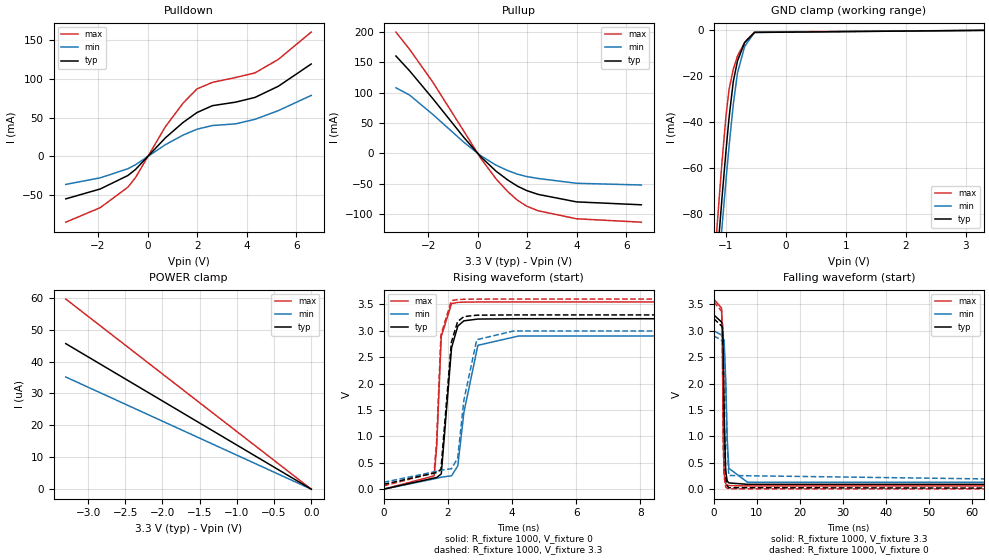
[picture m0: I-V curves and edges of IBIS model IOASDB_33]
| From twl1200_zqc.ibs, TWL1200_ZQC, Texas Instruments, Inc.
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[Model]   IOASDB_33
Model_type  I/O
Vinl=1.155
Vinh=2.145
Enable   Active-Low
Vref =   3.3
Rref =   1M
Cref =   15p
Vmeas =   1.65
| variable   typ   min   max
C_comp   3.59pF   2.93pF   4.64pF
| C_pullup   4.22pF   3.26pF   5.19pF
| C_pulldown   4.21pF   3.44pF   4.85pF
| C_tri-state   3.59pF   2.93pF   4.64pF
[Temperature Range]   40   100   -40
| Ambient temperature   25   85   -40
[Voltage range]   3.3   3   3.6
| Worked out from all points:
|   slope of the pulldown table from 0 to 0.495 V, typ, clamps not added: 29.3 ohm
|   slope of the pullup table from 0 to 0.495 V, typ, clamps not added: 24.1 ohm
|   GND clamp passes 1 mA (typ) near -0.53 V on its own axis
|   rising waveform, R_fixture 1000, V_fixture 0: 20-80 % time 221ps typ, 346ps min, 145ps max; typ from 0.003 V to 3.23 V
|   falling waveform, R_fixture 1000, V_fixture 3.3: 20-80 % time 375ps typ, 599ps min, 255ps max; typ from 3.3 V to 0.094 V
|   rising waveform, R_fixture 1000, V_fixture 3.3: 20-80 % time 215ps typ, 331ps min, 142ps max; typ from 0.094 V to 3.3 V
|   falling waveform, R_fixture 1000, V_fixture 0: 20-80 % time 370ps typ, 584ps min, 252ps max; typ from 3.23 V to 0.003 V
[GND Clamp]
| IOASDB_33
|   Voltage   I(typ)   I(min)   I(max)
-3.3V     -904.6mA   -884.4mA   -930.6mA
-1.16V    -105.2mA   -116.9mA   -90.79mA
-1.14V    -98.47mA   -110.4mA   -83.7mA
-1.105V   -86.8mA    -99.06mA   -71.53mA
-1.06V    -72.16mA   -84.8mA    -56.49mA
-995mV    -52.07mA   -64.93mA   -36.98mA
-945mV    -38.03mA   -50.49mA   -25.74mA
-875mV    -22.36mA   -32.37mA   -16.96mA
-805mV    -13.35mA   -18.54mA   -11.23mA
-685mV    -5.306mA   -6.994mA   -5.239mA
-520mV    -924.4uA   -895.8uA   -726uA
3.3V      560.6pA    3.201uA    -5.419uA
[POWER Clamp]
| IOASDB_33
|   Voltage   I(typ)   I(min)   I(max)
-3.3V     45.63uA    35.17uA    59.61uA
-1.795V   24.82uA    19.13uA    32.42uA
-1.53V    21.15uA    16.31uA    27.63uA
-1.435V   19.84uA    15.3uA     25.92uA
-1.06V    14.66uA    11.3uA     19.15uA
-745mV    10.3uA     7.944uA    13.46uA
0V        0A         0A         0A
[Pulldown]
| IOASDB_33
|   Voltage   I(typ)   I(min)   I(max)
-3.3V     -54.93mA   -36.27mA   -85.04mA
-1.91V    -42.15mA   -27.76mA   -66.25mA
-795mV    -24.76mA   -16.02mA   -39.87mA
-485mV    -16.89mA   -10.82mA   -27.31mA
715mV     23.78mA    15.01mA    38.15mA
1.43V     43.71mA    27.38mA    68.71mA
1.99V     56.48mA    34.95mA    86.98mA
2.61V     65.37mA    39.75mA    95.46mA
3.555V    69.97mA    41.95mA    101.8mA
4.33V     76.04mA    47.76mA    107.7mA
5.275V    90.5mA     59.02mA    125.2mA
6.6V      119.2mA    78.66mA    160.4mA
[Pullup]
| IOASDB_33
|   Voltage   I(typ)   I(min)   I(max)
-3.3V     160.1mA    108mA      199.4mA
-2.75V    135.8mA    95.9mA     171.1mA
-1.82V    90.5mA     64.41mA    117.7mA
-560mV    26.4mA     18.41mA    36.57mA
125mV     -5.592mA   -3.756mA   -8.169mA
740mV     -29.14mA   -19.25mA   -41.86mA
1.21V     -43.58mA   -28.1mA    -62.66mA
1.595V    -53.53mA   -33.93mA   -76.57mA
1.98V     -61.05mA   -37.98mA   -86.7mA
2.44V     -67.27mA   -41.13mA   -94.15mA
3.985V    -79.54mA   -48.98mA   -107.3mA
6.6V      -84.33mA   -51.79mA   -112.9mA
[Ramp]
| IOASDB_33
| variable   typ   min   max
dV/dt_r   1.94/2.32E-10   1.74/3.58E-10   2.13/1.50E-10
dV/dt_f   1.92/3.78E-10   1.72/6.00E-10   2.12/2.58E-10
R_load = 1000
[Rising Waveform]
| IOASDB_33
R_fixture =   1000
C_fixture =   0
L_fixture =   0
V_fixture =   0
V_fixture_min = 0
V_fixture_max = 0
|   Time   V(typ)   V(min)   V(max)
0s        3.396mV    3.432mV    3.422mV
1.575ns   214.3mV    198.5mV    255.6mV
1.65ns    222.8mV    209.5mV    793.3mV
1.795ns   291.7mV    230.6mV    2.894V
2.115ns   2.679V     256.3mV    3.513V
2.31ns    3.089V     444.2mV    3.537V
2.5ns     3.188V     1.456V     3.542V
2.935ns   3.222V     2.725V     3.545V
4.205ns   3.228V     2.901V     3.546V
240ns     3.229V     2.904V     3.547V
[Falling Waveform]
| IOASDB_33
R_fixture =   1000
C_fixture =   0
L_fixture =   0
V_fixture =   3.3
V_fixture_min = 3
V_fixture_max = 3.6
|   Time   V(typ)   V(min)   V(max)
0s        3.3V       3V         3.6V
1.815ns   3.165V     2.918V     3.428V
2.025ns   3.13V      2.881V     2.565V
2.2ns     2.626V     2.853V     975.6mV
2.39ns    1.49V      2.827V     309.8mV
2.765ns   343.7mV    2.084V     104.2mV
3.12ns    156.5mV    957.7mV    81.31mV
3.5ns     122mV      397.4mV    71.42mV
7.835ns   94.72mV    134.3mV    64.79mV
240ns     94.5mV     132.6mV    64.78mV
[Rising Waveform]
| IOASDB_33
R_fixture =   1000
C_fixture =   0
L_fixture =   0
V_fixture =   3.3
V_fixture_min = 3
V_fixture_max = 3.6
|   Time   V(typ)   V(min)   V(max)
0s        94.5mV     132.6mV    64.78mV
1.57ns    307.7mV    331.1mV    313.9mV
1.65ns    317mV      343mV      900.9mV
1.785ns   378.2mV    362.7mV    2.924V
2.11ns    2.783V     389.8mV    3.57V
2.305ns   3.175V     586.3mV    3.591V
2.5ns     3.268V     1.69V      3.596V
2.9ns     3.295V     2.831V     3.599V
4.055ns   3.3V       2.997V     3.6V
240ns     3.3V       3V         3.6V
[Falling Waveform]
| IOASDB_33
R_fixture =   1000
C_fixture =   0
L_fixture =   0
V_fixture =   0
V_fixture_min = 0
V_fixture_max = 0
|   Time   V(typ)   V(min)   V(max)
0s        3.229V     2.904V     3.547V
1.815ns   3.091V     2.821V     3.373V
1.92ns    3.075V     2.802V     3.182V
2.025ns   3.056V     2.783V     2.478V
2.19ns    2.583V     2.756V     944.5mV
2.385ns   1.386V     2.728V     249.4mV
2.755ns   256.4mV    1.965V     43.37mV
3.1ns     67.42mV    833.6mV    20.23mV
3.49ns    30.93mV    262.2mV    10.02mV
240ns     3.396mV    3.432mV    3.422mV
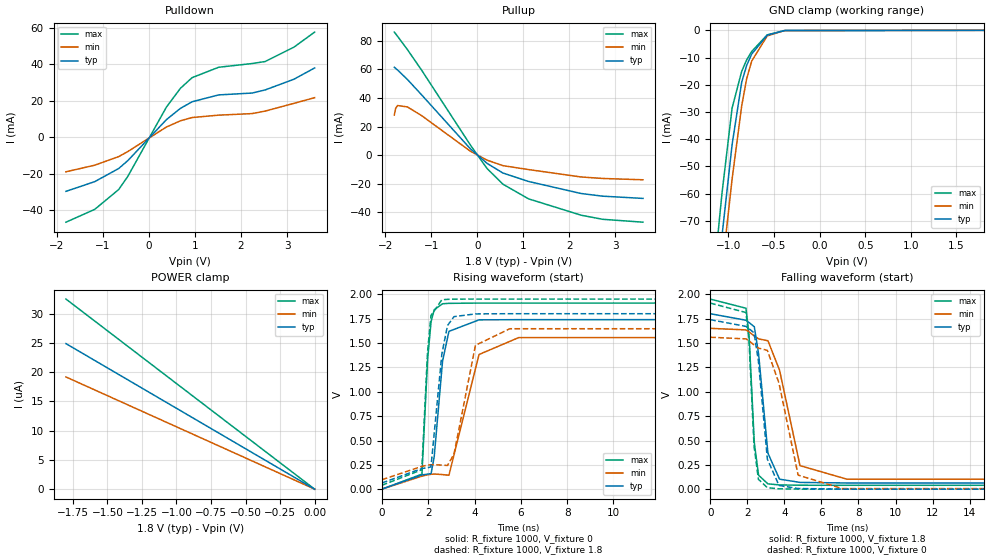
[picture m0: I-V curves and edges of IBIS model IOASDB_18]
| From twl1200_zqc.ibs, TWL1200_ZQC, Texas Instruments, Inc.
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[Model]   IOASDB_18
Model_type  I/O
Vinl=0.63
Vinh=1.17
Enable   Active-Low
Vref =   1.8
Rref =   1M
Cref =   15p
Vmeas =   0.9
| variable   typ   min   max
C_comp   3.84pF   3.22pF   4.64pF
| C_pullup   4.55pF   3.55pF   5.13pF
| C_pulldown   4.59pF   3.85pF   5.00pF
| C_tri-state   3.84pF   3.22pF   4.64pF
[Temperature Range]   40   100   -40
| Ambient temperature   25   85   -40
[Voltage range]   1.8   1.65   1.95
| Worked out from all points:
|   slope of the pulldown table from 0 to 0.27 V, typ, clamps not added: 38.1 ohm
|   slope of the pullup table from 0 to 0.27 V, typ, clamps not added: 38.7 ohm
|   GND clamp passes 1 mA (typ) near -0.53 V on its own axis
|   rising waveform, R_fixture 1000, V_fixture 0: 20-80 % time 402ps typ, 765ps min, 238ps max; typ from 0.002 V to 1.74 V
|   falling waveform, R_fixture 1000, V_fixture 1.8: 20-80 % time 507ps typ, 896ps min, 302ps max; typ from 1.8 V to 0.065 V
|   rising waveform, R_fixture 1000, V_fixture 1.8: 20-80 % time 379ps typ, 693ps min, 229ps max; typ from 0.065 V to 1.8 V
|   falling waveform, R_fixture 1000, V_fixture 0: 20-80 % time 493ps typ, 859ps min, 296ps max; typ from 1.74 V to 0.002 V
[GND Clamp]
| IOASDB_18
|   Voltage   I(typ)   I(min)   I(max)
-1.8V     -335.7mA   -338mA     -334.1mA
-1.155V   -103.5mA   -115.2mA   -88.97mA
-1.14V    -98.45mA   -110.3mA   -83.67mA
-1.1V     -85.13mA   -97.43mA   -69.79mA
-1.07V    -75.34mA   -87.92mA   -59.72mA
-960mV    -42.04mA   -54.71mA   -28.58mA
-855mV    -19.11mA   -27.85mA   -15.11mA
-800mV    -12.87mA   -17.76mA   -10.85mA
-745mV    -8.721mA   -11.32mA   -7.783mA
-575mV    -1.8mA     -2.053mA   -1.671mA
-385mV    -87.43uA   -83.76uA   -64.04uA
1.8V      356.9pA    1.602uA    -2.709uA
[POWER Clamp]
| IOASDB_18
|   Voltage   I(typ)   I(min)   I(max)
-1.8V     24.89uA    19.19uA    32.51uA
-205mV    2.835uA    2.188uA    3.703uA
-60mV     831.5nA    644.8nA    1.085uA
0V        0A         0A         0A
[Pulldown]
| IOASDB_18
|   Voltage   I(typ)   I(min)   I(max)
-1.8V     -29.66mA   -18.94mA   -46.6mA
-1.175V   -24.35mA   -15.32mA   -39.55mA
-655mV    -17.14mA   -10.59mA   -28.68mA
-455mV    -12.77mA   -7.807mA   -21.37mA
380mV     9.655mA    5.622mA    16.53mA
685mV     15.86mA    9.052mA    26.87mA
940mV     19.51mA    10.84mA    32.75mA
1.515V    23.26mA    12.15mA    38.43mA
2.24V     24.28mA    13mA       40.48mA
2.525V    25.99mA    14.38mA    41.58mA
3.15V     31.87mA    18.62mA    49.47mA
3.6V      38.06mA    21.75mA    57.74mA
[Pullup]
| IOASDB_18
|   Voltage   I(typ)   I(min)   I(max)
-1.8V     61.48mA    28.05mA    86.04mA
-1.77V    60.69mA    32.84mA    84.81mA
-1.73V    59.58mA    34.73mA    83.15mA
-1.515V   52.93mA    33.75mA    73.8mA
-1.21V    42.31mA    27.76mA    59.59mA
-150mV    4.562mA    2.859mA    7.243mA
215mV     -5.706mA   -3.438mA   -9.322mA
560mV     -12.45mA   -7.274mA   -20.24mA
1.115V    -18.32mA   -10.02mA   -30.47mA
2.255V    -26.73mA   -15.18mA   -41.88mA
2.725V    -28.6mA    -16.23mA   -44.77mA
3.6V      -30.17mA   -17.15mA   -46.78mA
[Ramp]
| IOASDB_18
| variable   typ   min   max
dV/dt_r   1.04/4.10E-10   0.93/7.70E-10   1.14/2.50E-10
dV/dt_f   1.04/5.11E-10   0.93/8.99E-10   1.14/3.07E-10
R_load = 1000
[Rising Waveform]
| IOASDB_18
R_fixture =   1000
C_fixture =   0
L_fixture =   0
V_fixture =   0
V_fixture_min = 0
V_fixture_max = 0
|   Time   V(typ)   V(min)   V(max)
0s        2.322mV    2.513mV    2.203mV
1.73ns    147.9mV    135.7mV    156mV
1.975ns   156.7mV    149.4mV    1.333V
2.125ns   161mV      154.6mV    1.719V
2.26ns    334.8mV    157.3mV    1.84V
2.62ns    1.314V     151.7mV    1.902V
2.895ns   1.619V     144.6mV    1.906V
4.195ns   1.737V     1.382V     1.909V
5.905ns   1.739V     1.555V     1.909V
239.9ns   1.739V     1.559V     1.909V
[Falling Waveform]
| IOASDB_18
R_fixture =   1000
C_fixture =   0
L_fixture =   0
V_fixture =   1.8
V_fixture_min = 1.65
V_fixture_max = 1.95
|   Time   V(typ)   V(min)   V(max)
0s        1.8V       1.65V      1.95V
1.93ns    1.733V     1.634V     1.856V
2.1ns     1.709V     1.613V     1.57V
2.38ns    1.666V     1.572V     477.6mV
2.61ns    1.391V     1.542V     145.2mV
3.115ns   371.3mV    1.523V     56.38mV
3.74ns    104.8mV    1.223V     45.63mV
4.845ns   71.35mV    243.4mV    42.53mV
7.38ns    65.72mV    104.3mV    42mV
239.9ns   65.27mV    98.8mV     41.98mV
[Rising Waveform]
| IOASDB_18
R_fixture =   1000
C_fixture =   0
L_fixture =   0
V_fixture =   1.8
V_fixture_min = 1.65
V_fixture_max = 1.95
|   Time   V(typ)   V(min)   V(max)
0s        65.27mV    98.8mV     41.98mV
1.725ns   213.4mV    235.5mV    201.3mV
1.97ns    222.1mV    248.5mV    1.401V
2.12ns    229.7mV    252.8mV    1.781V
2.59ns    1.387V     249mV      1.943V
2.835ns   1.679V     244.9mV    1.947V
3.115ns   1.77V      362.5mV    1.949V
4.04ns    1.798V     1.476V     1.95V
5.525ns   1.8V       1.646V     1.95V
239.9ns   1.8V       1.65V      1.95V
[Falling Waveform]
| IOASDB_18
R_fixture =   1000
C_fixture =   0
L_fixture =   0
V_fixture =   0
V_fixture_min = 0
V_fixture_max = 0
|   Time   V(typ)   V(min)   V(max)
0s        1.739V     1.559V     1.909V
1.93ns    1.67V      1.542V     1.812V
2.09ns    1.647V     1.522V     1.54V
2.365ns   1.604V     1.48V      446.3mV
2.6ns     1.317V     1.448V     103.8mV
3.085ns   310mV      1.424V     16.99mV
3.71ns    40.72mV    1.09V      5.875mV
4.745ns   8.732mV    146.1mV    2.818mV
7.12ns    2.841mV    8.381mV    2.227mV
239.9ns   2.322mV    2.513mV    2.203mV
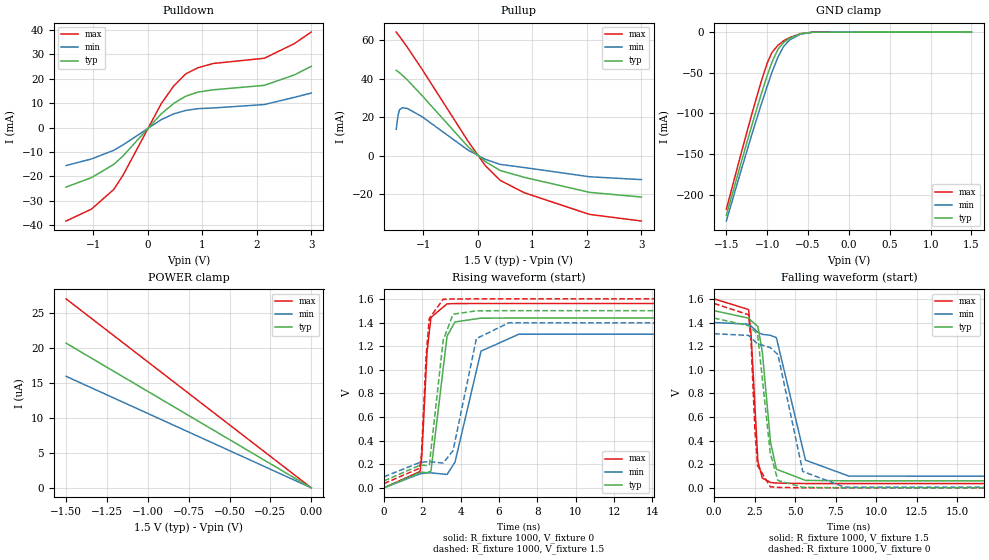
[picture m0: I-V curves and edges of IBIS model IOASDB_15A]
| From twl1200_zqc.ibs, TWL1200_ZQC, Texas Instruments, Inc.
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[Model]   IOASDB_15A
Model_type  I/O
Vinl=0.525
Vinh=0.975
Enable   Active-Low
Vref =   1.5
Rref =   1M
Cref =   15p
Vmeas =   0.75
| variable   typ   min   max
C_comp   3.91pF   3.32pF   4.64pF
| C_pullup   4.62pF   3.63pF   5.10pF
| C_pulldown   4.69pF   3.93pF   5.10pF
| C_tri-state   3.91pF   3.32pF   4.64pF
[Temperature Range]   40   100   -40
| Ambient temperature   25   85   -40
[Voltage range]   1.5   1.4   1.6
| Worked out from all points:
|   slope of the pulldown table from 0 to 0.225 V, typ, clamps not added: 43.2 ohm
|   slope of the pullup table from 0 to 0.225 V, typ, clamps not added: 47.4 ohm
|   GND clamp passes 1 mA (typ) near -0.53 V on its own axis
|   rising waveform, R_fixture 1000, V_fixture 0: 20-80 % time 531ps typ, 1.01ns min, 305ps max; typ from 0.002 V to 1.44 V
|   falling waveform, R_fixture 1000, V_fixture 1.5: 20-80 % time 597ps typ, 1.07ns min, 328ps max; typ from 1.5 V to 0.061 V
|   rising waveform, R_fixture 1000, V_fixture 1.5: 20-80 % time 494ps typ, 895ps min, 292ps max; typ from 0.061 V to 1.5 V
|   falling waveform, R_fixture 1000, V_fixture 0: 20-80 % time 578ps typ, 1.01ns min, 320ps max; typ from 1.44 V to 0.002 V
[GND Clamp]
| IOASDB_15A
|   Voltage   I(typ)   I(min)   I(max)
-1.5V     -225.5mA   -232.3mA   -217.8mA
-1.315V   -159mA     -168.6mA   -147.6mA
-1.175V   -110.3mA   -121.8mA   -96.11mA
-1.07V    -75.34mA   -87.91mA   -59.72mA
-1V       -53.52mA   -66.39mA   -38.29mA
-940mV    -36.69mA   -49.08mA   -24.84mA
-870mV    -21.47mA   -31.19mA   -16.46mA
-800mV    -12.87mA   -17.76mA   -10.85mA
-725mV    -7.452mA   -9.662mA   -6.863mA
-590mV    -2.11mA    -2.522mA   -2.033mA
-445mV    -250.8uA   -238.2uA   -152.1uA
1.5V      322.6pA    1.07uA     -1.806uA
[POWER Clamp]
| IOASDB_15A
|   Voltage   I(typ)   I(min)   I(max)
-1.5V     20.74uA    15.99uA    27.09uA
-60mV     831.2nA    644.6nA    1.085uA
-5mV      69.54nA    55.09nA    90.39nA
0V        0A         0A         0A
[Pulldown]
| IOASDB_15A
|   Voltage   I(typ)   I(min)   I(max)
-1.5V     -24.33mA   -15.51mA   -38.22mA
-1.035V   -20.48mA   -12.84mA   -33.36mA
-625mV    -15.07mA   -9.288mA   -25.31mA
-450mV    -11.5mA    -7.006mA   -19.3mA
245mV     5.598mA    3.228mA    9.739mA
475mV     9.882mA    5.606mA    17.01mA
695mV     12.83mA    7.023mA    21.96mA
920mV     14.52mA    7.745mA    24.48mA
1.2V      15.46mA    8.034mA    26.23mA
2.14V     17.29mA    9.424mA    28.38mA
2.69V     21.55mA    12.38mA    34.36mA
3V        25.05mA    14.12mA    39.1mA
[Pullup]
| IOASDB_15A
|   Voltage   I(typ)   I(min)   I(max)
-1.5V     44.25mA    13.7mA     64.07mA
-1.465V   43.53mA    21.15mA    62.77mA
-1.44V    42.97mA    23.84mA    61.83mA
-1.385V   41.65mA    24.88mA    59.71mA
-1.295V   39.27mA    24.5mA     56.15mA
-1.03V    31.3mA     20.32mA    45mA
-180mV    4.667mA    2.918mA    7.495mA
135mV     -3.014mA   -1.803mA   -5.058mA
410mV     -7.634mA   -4.45mA    -12.73mA
850mV     -11.14mA   -6.08mA    -19.1mA
2.05V     -18.92mA   -10.84mA   -30.33mA
3V        -21.34mA   -12.32mA   -33.75mA
[Ramp]
| IOASDB_15A
| variable   typ   min   max
dV/dt_r   0.86/5.37E-10   0.78/1.01E-09   0.94/3.19E-10
dV/dt_f   0.86/6.04E-10   0.78/1.07E-09   0.94/3.40E-10
R_load = 1000
[Rising Waveform]
| IOASDB_15A
R_fixture =   1000
C_fixture =   0
L_fixture =   0
V_fixture =   0
V_fixture_min = 0
V_fixture_max = 0
|   Time   V(typ)   V(min)   V(max)
0s        2.155mV    2.395mV    1.989mV
1.885ns   131.1mV    120.9mV    140.8mV
1.975ns   133.6mV    123.4mV    272.9mV
2.245ns   129.9mV    127.5mV    1.146V
2.45ns    143.4mV    128.9mV    1.443V
3.29ns    1.285V     115.2mV    1.558V
3.705ns   1.405V     219.4mV    1.56V
5.06ns    1.437V     1.158V     1.561V
7.03ns    1.438V     1.301V     1.561V
239.9ns   1.438V     1.305V     1.561V
[Falling Waveform]
| IOASDB_15A
R_fixture =   1000
C_fixture =   0
L_fixture =   0
V_fixture =   1.5
V_fixture_min = 1.4
V_fixture_max = 1.6
|   Time   V(typ)   V(min)   V(max)
0s        1.5V       1.4V       1.6V
2.125ns   1.437V     1.386V     1.51V
2.285ns   1.415V     1.369V     1.289V
2.7ns     1.367V     1.318V     225.7mV
2.975ns   1.15V      1.3V       84.3mV
3.48ns    387.2mV    1.292V     47.8mV
3.84ns    159.9mV    1.272V     42.66mV
5.635ns   64.87mV    235.8mV    38.32mV
8.31ns    61.28mV    101.3mV    38.08mV
239.9ns   60.96mV    95.19mV    38.07mV
[Rising Waveform]
| IOASDB_15A
R_fixture =   1000
C_fixture =   0
L_fixture =   0
V_fixture =   1.5
V_fixture_min = 1.4
V_fixture_max = 1.6
|   Time   V(typ)   V(min)   V(max)
0s        60.96mV    95.19mV    38.07mV
1.85ns    191.2mV    215.5mV    167mV
1.955ns   193.8mV    218.3mV    284.8mV
2.2ns     191.3mV    222mV      1.121V
2.365ns   194.8mV    223.3mV    1.435V
3.09ns    1.252V     211.8mV    1.597V
3.605ns   1.47V      317.5mV    1.599V
4.82ns    1.499V     1.264V     1.6V
6.505ns   1.5V       1.397V     1.6V
239.9ns   1.5V       1.4V       1.6V
[Falling Waveform]
| IOASDB_15A
R_fixture =   1000
C_fixture =   0
L_fixture =   0
V_fixture =   0
V_fixture_min = 0
V_fixture_max = 0
|   Time   V(typ)   V(min)   V(max)
0s        1.438V     1.305V     1.561V
2.125ns   1.373V     1.291V     1.466V
2.27ns    1.352V     1.274V     1.261V
2.52ns    1.324V     1.239V     479.7mV
2.68ns    1.301V     1.22V      189.6mV
3.465ns   293.8mV    1.188V     11.19mV
3.935ns   64.38mV    1.129V     5.715mV
5.465ns   6.425mV    140.9mV    2.29mV
8.035ns   2.517mV    8.136mV    1.999mV
239.9ns   2.155mV    2.395mV    1.989mV
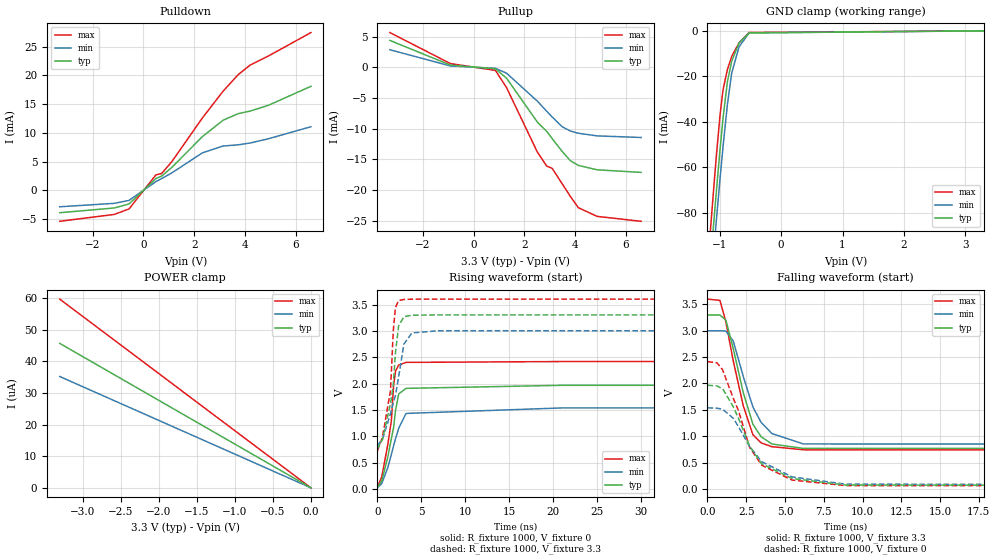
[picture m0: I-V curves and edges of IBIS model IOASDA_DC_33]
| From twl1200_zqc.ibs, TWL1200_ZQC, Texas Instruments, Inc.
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[Model]   IOASDA_DC_33
Model_type  I/O
Vinl=1.155
Vinh=2.145
Enable   Active-Low
Vref =   3.3
Rref =   1M
Cref =   15p
Vmeas =   1.65
| variable   typ   min   max
C_comp   3.59pF   2.93pF   4.64pF
| C_pullup   3.59pF   2.92pF   4.58pF
| C_pulldown   3.88pF   3.06pF   4.87pF
| C_tri-state   3.59pF   2.93pF   4.64pF
[Temperature Range]   40   100   -40
| Ambient temperature   25   85   -40
[Voltage range]   3.3   3   3.6
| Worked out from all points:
|   slope of the pulldown table from 0 to 0.495 V, typ, clamps not added: 231 ohm
|   slope of the pullup table from 0 to 0.495 V, typ, clamps not added: 4.28 kohm
|   GND clamp passes 1 mA (typ) near -0.53 V on its own axis
|   rising waveform, R_fixture 1000, V_fixture 0: 20-80 % time 1.19ns typ, 1.53ns min, 990ps max; typ from 0.023 V to 1.97 V
|   falling waveform, R_fixture 1000, V_fixture 3.3: 20-80 % time 1.31ns typ, 1.55ns min, 1.27ns max; typ from 3.3 V to 0.754 V
|   rising waveform, R_fixture 1000, V_fixture 3.3: 20-80 % time 1.1ns typ, 1.55ns min, 881ps max; typ from 0.754 V to 3.3 V
|   falling waveform, R_fixture 1000, V_fixture 0: 20-80 % time 2.13ns typ, 2.6ns min, 1.88ns max; typ from 1.97 V to 0.023 V
[GND Clamp]
| IOASDA_DC_33
|   Voltage   I(typ)   I(min)   I(max)
-3.3V     -904.6mA   -884.4mA   -930.6mA
-1.16V    -105.2mA   -116.9mA   -90.79mA
-1.14V    -98.47mA   -110.4mA   -83.7mA
-1.105V   -86.8mA    -99.06mA   -71.53mA
-1.06V    -72.16mA   -84.8mA    -56.49mA
-995mV    -52.07mA   -64.93mA   -36.98mA
-945mV    -38.03mA   -50.49mA   -25.74mA
-875mV    -22.36mA   -32.37mA   -16.96mA
-805mV    -13.35mA   -18.54mA   -11.23mA
-685mV    -5.306mA   -6.994mA   -5.239mA
-520mV    -924.4uA   -895.8uA   -726uA
3.3V      560.6pA    3.201uA    -5.419uA
[POWER Clamp]
| IOASDA_DC_33
|   Voltage   I(typ)   I(min)   I(max)
-3.3V     45.63uA    35.17uA    59.61uA
-1.795V   24.82uA    19.13uA    32.42uA
-1.53V    21.15uA    16.31uA    27.63uA
-1.435V   19.84uA    15.3uA     25.92uA
-1.06V    14.66uA    11.3uA     19.15uA
-745mV    10.3uA     7.944uA    13.46uA
0V        0A         0A         0A
[Pulldown]
| IOASDA_DC_33
|   Voltage   I(typ)   I(min)   I(max)
-3.3V     -3.9mA     -2.867mA   -5.392mA
-1.145V   -3.071mA   -2.265mA   -4.194mA
-570mV    -2.374mA   -1.756mA   -3.24mA
490mV     2.043mA    1.513mA    2.68mA
715mV     2.469mA    2.037mA    2.924mA
1.11V     3.956mA    3.012mA    4.939mA
2.33V     9.373mA    6.537mA    12.64mA
3.145V    12.21mA    7.704mA    17.28mA
3.735V    13.34mA    7.914mA    20.13mA
4.195V    13.77mA    8.219mA    21.76mA
4.925V    14.79mA    8.967mA    23.37mA
6.6V      18.09mA    11.06mA    27.44mA
[Pullup]
| IOASDA_DC_33
|   Voltage   I(typ)   I(min)   I(max)
-3.3V     4.399mA    2.88mA     5.68mA
-915mV    378.9uA    237.3uA    624uA
860mV     -228.3uA   -143uA     -486.4uA
1.3V      -1.764mA   -946.4uA   -3.307mA
2.515V    -8.924mA   -5.506mA   -13.82mA
2.885V    -10.44mA   -7.158mA   -16.1mA
3.095V    -11.6mA    -8.077mA   -16.44mA
3.49V     -13.69mA   -9.666mA   -18.96mA
3.815V    -15.21mA   -10.37mA   -21.04mA
4.13V     -15.97mA   -10.73mA   -22.87mA
4.87V     -16.69mA   -11.16mA   -24.28mA
6.6V      -17.11mA   -11.42mA   -25.08mA
[Ramp]
| IOASDA_DC_33
| variable   typ   min   max
dV/dt_r   1.17/1.20E-09   0.91/1.53E-09   1.43/9.92E-10
dV/dt_f   1.53/1.31E-09   1.31/1.56E-09   1.73/1.27E-09
R_load = 1000
[Rising Waveform]
| IOASDA_DC_33
R_fixture =   1000
C_fixture =   0
L_fixture =   0
V_fixture =   0
V_fixture_min = 0
V_fixture_max = 0
|   Time   V(typ)   V(min)   V(max)
0s        22.96mV    18.97mV    29.38mV
505ps     154.5mV    100.8mV    227.5mV
1.19ns    602mV      403mV      838.9mV
1.595ns   950.1mV    650mV      1.289V
1.855ns   1.165V     822.7mV    1.963V
2.07ns    1.489V     950.3mV    2.236V
2.44ns    1.804V     1.154V     2.351V
3.27ns    1.908V     1.432V     2.401V
21.1ns    1.966V     1.537V     2.417V
240ns     1.966V     1.538V     2.416V
[Falling Waveform]
| IOASDA_DC_33
R_fixture =   1000
C_fixture =   0
L_fixture =   0
V_fixture =   3.3
V_fixture_min = 3
V_fixture_max = 3.6
|   Time   V(typ)   V(min)   V(max)
0s        3.3V       3V         3.6V
805ps     3.298V     3V         3.576V
1.19ns    3.201V     2.994V     3.169V
1.66ns    2.666V     2.809V     2.434V
2.305ns   1.831V     2.138V     1.581V
2.93ns    1.228V     1.554V     1.028V
3.455ns   992mV      1.265V     874.3mV
4.155ns   851.1mV    1.05V      800.2mV
6.185ns   768.2mV    852.4mV    742.3mV
240ns     753.8mV    823.6mV    717.8mV
[Rising Waveform]
| IOASDA_DC_33
R_fixture =   1000
C_fixture =   0
L_fixture =   0
V_fixture =   3.3
V_fixture_min = 3
V_fixture_max = 3.6
|   Time   V(typ)   V(min)   V(max)
0s        753.8mV    823.6mV    717.8mV
590ps     940.2mV    944.2mV    986.9mV
1.495ns   1.615V     1.425V     1.863V
1.815ns   1.966V     1.632V     2.993V
2.055ns   2.57V      1.766V     3.438V
2.42ns    3.092V     2.123V     3.574V
3.025ns   3.268V     2.748V     3.596V
3.93ns    3.296V     2.96V      3.601V
6.91ns    3.303V     3.002V     3.602V
240ns     3.3V       3V         3.6V
[Falling Waveform]
| IOASDA_DC_33
R_fixture =   1000
C_fixture =   0
L_fixture =   0
V_fixture =   0
V_fixture_min = 0
V_fixture_max = 0
|   Time   V(typ)   V(min)   V(max)
0s        1.966V     1.538V     2.416V
615ps     1.953V     1.53V      2.391V
975ps     1.902V     1.512V     2.262V
1.66ns    1.562V     1.341V     1.724V
2ns       1.341V     1.181V     1.485V
2.72ns    810.1mV    804.2mV    787.3mV
3.5ns     476mV      515.4mV    448.6mV
5.46ns    197.4mV    227.1mV    166.9mV
8.91ns    72.84mV    89.21mV    62.21mV
240ns     23.3mV     19.32mV    29.81mV
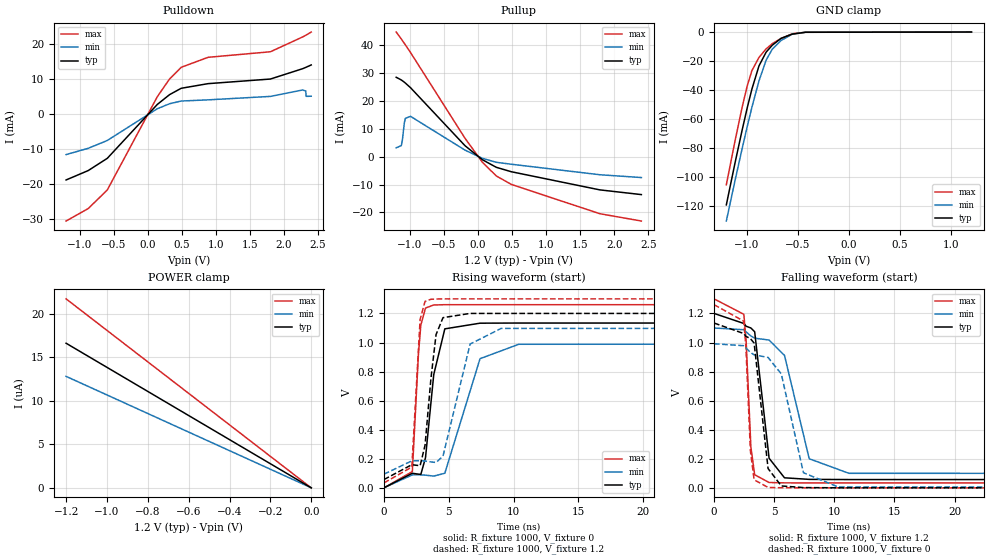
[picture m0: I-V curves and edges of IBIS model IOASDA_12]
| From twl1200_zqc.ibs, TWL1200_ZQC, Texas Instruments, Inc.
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[Model]   IOASDA_12
Model_type  I/O
Vinl=0.24
Vinh=0.96
Enable   Active-Low
Vref =   1.2
Rref =   1M
Cref =   15p
Vmeas =   0.6
| variable   typ   min   max
C_comp   3.98pF   3.44pF   4.66pF
| C_pullup   4.69pF   3.74pF   5.10pF
| C_pulldown   4.78pF   3.91pF   5.20pF
| C_tri-state   3.98pF   3.44pF   4.66pF
[Temperature Range]   40   100   -40
| Ambient temperature   25   85   -40
[Voltage range]   1.2   1.1   1.3
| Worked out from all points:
|   slope of the pulldown table from 0 to 0.18 V, typ, clamps not added: 53.1 ohm
|   slope of the pullup table from 0 to 0.18 V, typ, clamps not added: 64.5 ohm
|   GND clamp passes 1 mA (typ) near -0.53 V on its own axis
|   rising waveform, R_fixture 1000, V_fixture 0: 20-80 % time 792ps typ, 1.7ns min, 404ps max; typ from 0.002 V to 1.13 V
|   falling waveform, R_fixture 1000, V_fixture 1.2: 20-80 % time 780ps typ, 1.54ns min, 414ps max; typ from 1.2 V to 0.059 V
|   rising waveform, R_fixture 1000, V_fixture 1.2: 20-80 % time 714ps typ, 1.43ns min, 379ps max; typ from 0.059 V to 1.2 V
|   falling waveform, R_fixture 1000, V_fixture 0: 20-80 % time 749ps typ, 1.44ns min, 401ps max; typ from 1.13 V to 0.002 V
[GND Clamp]
| IOASDA_12
|   Voltage   I(typ)   I(min)   I(max)
-1.2V     -118.9mA   -130mA     -105.1mA
-1.115V   -90.07mA   -102.2mA   -74.93mA
-1.045V   -67.35mA   -80.09mA   -51.64mA
-995mV    -52.03mA   -64.9mA    -36.94mA
-950mV    -39.32mA   -51.86mA   -26.6mA
-880mV    -23.22mA   -33.52mA   -17.4mA
-810mV    -13.78mA   -19.31mA   -11.53mA
-750mV    -9.045mA   -11.77mA   -8.009mA
-665mV    -4.38mA    -5.831mA   -4.423mA
-555mV    -1.418mA   -1.522mA   -1.23mA
-425mV    -166.4uA   -161.6uA   -98.99uA
1.2V      289.9pA    1.07uA     -1.806uA
[POWER Clamp]
| IOASDA_12
|   Voltage   I(typ)   I(min)   I(max)
-1.2V     16.59uA    12.79uA    21.68uA
-60mV     831nA      644.3nA    1.084uA
-5mV      69.5nA     55.02nA    90.38nA
0V        0A         0A         0A
[Pulldown]
| IOASDA_12
|   Voltage   I(typ)   I(min)   I(max)
-1.2V     -18.88mA   -11.64mA   -30.59mA
-875mV    -16.2mA    -9.853mA   -27.04mA
-595mV    -12.71mA   -7.617mA   -21.74mA
140mV     2.672mA    1.446mA    4.878mA
320mV     5.463mA    2.867mA    9.939mA
490mV     7.271mA    3.638mA    13.25mA
885mV     8.596mA    3.97mA     16.11mA
1.8V      9.909mA    4.956mA    17.69mA
2.275V    12.87mA    6.799mA    21.93mA
2.32V     13.24mA    6.483mA    22.4mA
2.325V    13.28mA    4.966mA    22.45mA
2.4V      13.93mA    5.007mA    23.32mA
[Pullup]
| IOASDA_12
|   Voltage   I(typ)   I(min)   I(max)
-1.2V     28.37mA    3.135mA    44.56mA
-1.125V   27.41mA    3.923mA    42.05mA
-1.11V    27.15mA    5.792mA    41.53mA
-1.08V    26.59mA    12.16mA    40.49mA
-1.065V   26.29mA    13.7mA     39.95mA
-990mV    24.65mA    14.4mA     37.24mA
-190mV    3.9mA      2.315mA    6.56mA
65mV      -1.117mA   -620.4uA   -2.013mA
270mV     -3.838mA   -2.052mA   -6.935mA
490mV     -5.42mA    -2.732mA   -9.944mA
1.79V     -11.91mA   -6.499mA   -20.44mA
2.4V      -13.6mA    -7.5mA     -23.05mA
[Ramp]
| IOASDA_12
| variable   typ   min   max
dV/dt_r   0.68/7.97E-10   0.59/1.71E-09   0.75/4.09E-10
dV/dt_f   0.68/7.85E-10   0.60/1.54E-09   0.76/4.20E-10
R_load = 1000
[Rising Waveform]
| IOASDA_12
R_fixture =   1000
C_fixture =   0
L_fixture =   0
V_fixture =   0
V_fixture_min = 0
V_fixture_max = 0
|   Time   V(typ)   V(min)   V(max)
0s        2.048mV    2.342mV    1.853mV
2.19ns    102.1mV    90.83mV    113.5mV
2.66ns    96.05mV    91.57mV    919.7mV
2.845ns   94.13mV    91.11mV    1.12V
3.205ns   208.8mV    89.03mV    1.237V
3.84ns    779.6mV    82.66mV    1.258V
4.695ns   1.094V     102.1mV    1.26V
7.41ns    1.133V     889mV      1.26V
10.4ns    1.134V     988.2mV    1.26V
239.9ns   1.134V     991.6mV    1.26V
[Falling Waveform]
| IOASDA_12
R_fixture =   1000
C_fixture =   0
L_fixture =   0
V_fixture =   1.2
V_fixture_min = 1.1
V_fixture_max = 1.3
|   Time   V(typ)   V(min)   V(max)
0s        1.2V       1.1V       1.3V
2.475ns   1.131V     1.088V     1.194V
2.665ns   1.112V     1.073V     1.012V
3.06ns    1.1V       1.045V     282.2mV
3.375ns   1.074V     1.03V      91.87mV
4.575ns   205mV      1.017V     38.54mV
5.855ns   70.83mV    911.6mV    36.16mV
7.91ns    60.08mV    201.8mV    35.79mV
11.21ns   58.84mV    101.7mV    35.76mV
239.9ns   58.75mV    95.77mV    35.76mV
[Rising Waveform]
| IOASDA_12
R_fixture =   1000
C_fixture =   0
L_fixture =   0
V_fixture =   1.2
V_fixture_min = 1.1
V_fixture_max = 1.3
|   Time   V(typ)   V(min)   V(max)
0s        58.75mV    95.77mV    35.76mV
2.15ns    160.9mV    187.1mV    144.8mV
2.79ns    153.8mV    188.8mV    1.159V
3.17ns    295.1mV    185.8mV    1.283V
3.625ns   754.1mV    179.9mV    1.297V
4.02ns    1.055V     175.9mV    1.299V
4.555ns   1.171V     219.9mV    1.3V
6.645ns   1.2V       989.4mV    1.3V
9.035ns   1.2V       1.097V     1.3V
239.9ns   1.2V       1.1V       1.3V
[Falling Waveform]
| IOASDA_12
R_fixture =   1000
C_fixture =   0
L_fixture =   0
V_fixture =   0
V_fixture_min = 0
V_fixture_max = 0
|   Time   V(typ)   V(min)   V(max)
0s        1.134V     991.6mV    1.26V
2.465ns   1.062V     978.2mV    1.147V
2.64ns    1.043V     963.6mV    978.8mV
3.02ns    1.027V     932.2mV    255.7mV
3.33ns    996.1mV    915.4mV    57.11mV
4.49ns    134.4mV    897.6mV    4.702mV
5.59ns    14.96mV    784.3mV    2.374mV
7.43ns    3.654mV    105.6mV    1.898mV
10.32ns   2.195mV    7.983mV    1.854mV
239.9ns   2.048mV    2.342mV    1.853mV
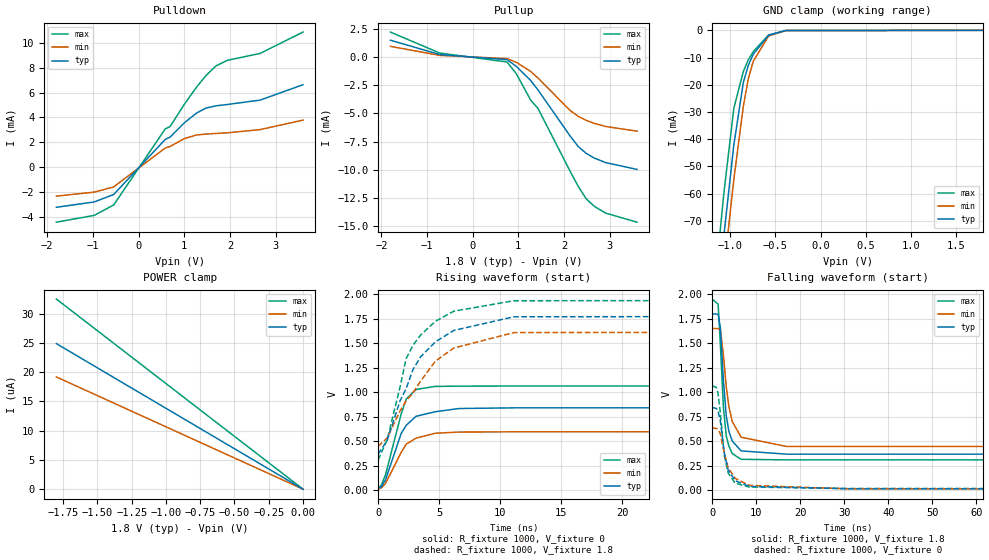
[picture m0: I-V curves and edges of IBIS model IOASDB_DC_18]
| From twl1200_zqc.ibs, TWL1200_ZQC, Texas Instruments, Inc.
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[Model]   IOASDB_DC_18
Model_type  I/O
Vinl=0.63
Vinh=1.17
Enable   Active-Low
Vref =   1.8
Rref =   1M
Cref =   15p
Vmeas =   0.9
| variable   typ   min   max
C_comp   3.84pF   3.22pF   4.64pF
| C_pullup   3.82pF   3.21pF   4.41pF
| C_pulldown   4.14pF   3.41pF   4.86pF
| C_tri-state   3.84pF   3.22pF   4.64pF
[Temperature Range]   40   100   -40
| Ambient temperature   25   85   -40
[Voltage range]   1.8   1.65   1.95
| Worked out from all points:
|   slope of the pulldown table from 0 to 0.27 V, typ, clamps not added: 244 ohm
|   slope of the pullup table from 0 to 0.27 V, typ, clamps not added: 4.38 kohm
|   GND clamp passes 1 mA (typ) near -0.53 V on its own axis
|   rising waveform, R_fixture 1000, V_fixture 0: 20-80 % time 1.55ns typ, 1.54ns min, 1.28ns max; typ from 0.013 V to 0.844 V
|   falling waveform, R_fixture 1000, V_fixture 1.8: 20-80 % time 1.48ns typ, 2.15ns min, 1.2ns max; typ from 1.8 V to 0.368 V
|   rising waveform, R_fixture 1000, V_fixture 1.8: 20-80 % time 3.55ns typ, 4.29ns min, 2.77ns max; typ from 0.368 V to 1.8 V
|   falling waveform, R_fixture 1000, V_fixture 0: 20-80 % time 1.94ns typ, 2.69ns min, 1.55ns max; typ from 0.844 V to 0.013 V
[GND Clamp]
| IOASDB_DC_18
|   Voltage   I(typ)   I(min)   I(max)
-1.8V     -335.7mA   -338mA     -334.1mA
-1.155V   -103.5mA   -115.2mA   -88.97mA
-1.14V    -98.45mA   -110.3mA   -83.67mA
-1.1V     -85.13mA   -97.43mA   -69.79mA
-1.07V    -75.34mA   -87.92mA   -59.72mA
-960mV    -42.04mA   -54.71mA   -28.58mA
-855mV    -19.11mA   -27.85mA   -15.11mA
-800mV    -12.87mA   -17.76mA   -10.85mA
-745mV    -8.721mA   -11.32mA   -7.783mA
-575mV    -1.8mA     -2.053mA   -1.671mA
-385mV    -87.43uA   -83.76uA   -64.04uA
1.8V      356.9pA    1.602uA    -2.709uA
[POWER Clamp]
| IOASDB_DC_18
|   Voltage   I(typ)   I(min)   I(max)
-1.8V     24.89uA    19.19uA    32.51uA
-205mV    2.835uA    2.188uA    3.703uA
-60mV     831.5nA    644.8nA    1.085uA
0V        0A         0A         0A
[Pulldown]
| IOASDB_DC_18
|   Voltage   I(typ)   I(min)   I(max)
-1.8V     -3.214mA   -2.319mA   -4.411mA
-970mV    -2.785mA   -1.998mA   -3.864mA
-545mV    -2.186mA   -1.579mA   -3.028mA
585mV     2.237mA    1.546mA    3.08mA
690mV     2.42mA     1.666mA    3.264mA
1.005V    3.577mA    2.306mA    5.071mA
1.275V    4.362mA    2.594mA    6.456mA
1.475V    4.746mA    2.662mA    7.356mA
1.695V    4.93mA     2.713mA    8.135mA
1.945V    5.038mA    2.763mA    8.587mA
2.66V     5.388mA    3.021mA    9.134mA
3.6V      6.624mA    3.782mA    10.85mA
[Pullup]
| IOASDB_DC_18
|   Voltage   I(typ)   I(min)   I(max)
-1.8V     1.482mA    937.7uA    2.202mA
-720mV    211.8uA    136.5uA    344.3uA
755mV     -242.7uA   -145.3uA   -448.4uA
960mV     -848uA     -485uA     -1.507mA
1.27V     -2.08mA    -1.279mA   -3.819mA
1.43V     -2.915mA   -1.863mA   -4.554mA
2.14V     -7.034mA   -4.758mA   -10.17mA
2.31V     -7.924mA   -5.258mA   -11.45mA
2.485V    -8.539mA   -5.616mA   -12.56mA
2.665V    -8.961mA   -5.888mA   -13.24mA
2.915V    -9.363mA   -6.163mA   -13.84mA
3.6V      -9.963mA   -6.576mA   -14.64mA
[Ramp]
| IOASDB_DC_18
| variable   typ   min   max
dV/dt_r   0.50/1.55E-09   0.36/1.54E-09   0.63/1.29E-09
dV/dt_f   0.86/1.48E-09   0.72/2.15E-09   0.98/1.21E-09
R_load = 1000
[Rising Waveform]
| IOASDB_DC_18
R_fixture =   1000
C_fixture =   0
L_fixture =   0
V_fixture =   0
V_fixture_min = 0
V_fixture_max = 0
|   Time   V(typ)   V(min)   V(max)
0s        13.03mV    11.14mV    16.26mV
270ps     36.42mV    24.76mV    53.27mV
615ps     109.2mV    70.04mV    161.3mV
1.89ns    579.6mV    386.5mV    778.5mV
2.31ns    663.4mV    470.8mV    931.9mV
3.105ns   754.5mV    531.2mV    1.028V
4.67ns    800.7mV    581.8mV    1.059V
6.64ns    833.7mV    593.5mV    1.062V
11.24ns   840.7mV    596.3mV    1.063V
240ns     844.2mV    612mV      1.065V
[Falling Waveform]
| IOASDB_DC_18
R_fixture =   1000
C_fixture =   0
L_fixture =   0
V_fixture =   1.8
V_fixture_min = 1.65
V_fixture_max = 1.95
|   Time   V(typ)   V(min)   V(max)
0s        1.8V       1.65V      1.95V
1.36ns    1.796V     1.649V     1.898V
1.86ns    1.66V      1.637V     1.495V
2.555ns   1.118V     1.382V     845.6mV
3.21ns    759.2mV    1.053V     554.1mV
3.795ns   601.8mV    856.9mV    450.6mV
4.56ns    503.2mV    701.6mV    374.3mV
6.58ns    401.8mV    541.2mV    316mV
16.88ns   368.4mV    447.1mV    310.1mV
240ns     368.3mV    446.4mV    309.4mV
[Rising Waveform]
| IOASDB_DC_18
R_fixture =   1000
C_fixture =   0
L_fixture =   0
V_fixture =   1.8
V_fixture_min = 1.65
V_fixture_max = 1.95
|   Time   V(typ)   V(min)   V(max)
0s        368.2mV    446.4mV    309.3mV
735ps     506.3mV    532.9mV    511.5mV
1.81ns    916.1mV    812.5mV    1.06V
2.29ns    1.034V     910.5mV    1.341V
2.85ns    1.23V      992.2mV    1.478V
3.48ns    1.361V     1.113V     1.583V
4.685ns   1.513V     1.317V     1.723V
6.19ns    1.63V      1.45V      1.826V
11.1ns    1.769V     1.608V     1.933V
240ns     1.8V       1.65V      1.95V
[Falling Waveform]
| IOASDB_DC_18
R_fixture =   1000
C_fixture =   0
L_fixture =   0
V_fixture =   0
V_fixture_min = 0
V_fixture_max = 0
|   Time   V(typ)   V(min)   V(max)
0s        844.2mV    637.3mV    1.064V
925ps     835.4mV    630.4mV    1.051V
1.305ns   816.4mV    623.7mV    999.2mV
1.87ns    703.2mV    575.8mV    787mV
2.76ns    381mV      374.4mV    352.9mV
3.64ns    206.5mV    230.5mV    174.6mV
5.245ns   97.05mV    121.6mV    71.8mV
8.455ns   39.37mV    50.27mV    33.14mV
30.81ns   15.87mV    14.9mV     18.5mV
240ns     13.31mV    11.48mV    16.5mV
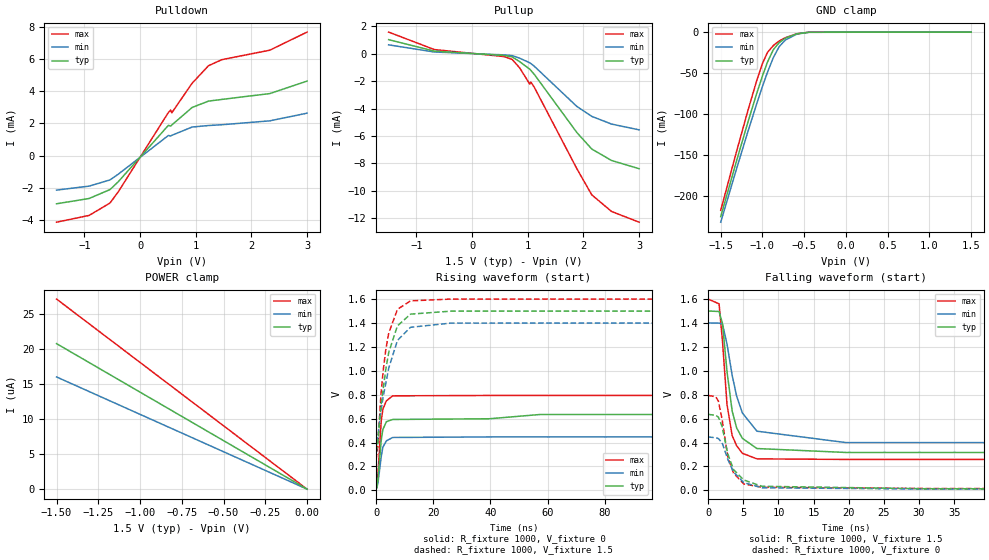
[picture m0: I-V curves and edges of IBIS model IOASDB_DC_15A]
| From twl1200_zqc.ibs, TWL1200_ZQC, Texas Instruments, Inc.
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[Model]   IOASDB_DC_15A
Model_type  I/O
Vinl=0.525
Vinh=0.975
Enable   Active-Low
Vref =   1.5
Rref =   1M
Cref =   15p
Vmeas =   0.75
| variable   typ   min   max
C_comp   3.91pF   3.32pF   4.64pF
| C_pullup   3.89pF   3.30pF   4.43pF
| C_pulldown   4.21pF   3.46pF   4.87pF
| C_tri-state   3.91pF   3.32pF   4.64pF
[Temperature Range]   40   100   -40
| Ambient temperature   25   85   -40
[Voltage range]   1.5   1.4   1.6
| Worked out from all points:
|   slope of the pulldown table from 0 to 0.225 V, typ, clamps not added: 254 ohm
|   slope of the pullup table from 0 to 0.225 V, typ, clamps not added: 4.42 kohm
|   GND clamp passes 1 mA (typ) near -0.53 V on its own axis
|   rising waveform, R_fixture 1000, V_fixture 0: 20-80 % time 1.57ns typ, 1.48ns min, 1.37ns max; typ from 0.011 V to 0.636 V
|   falling waveform, R_fixture 1000, V_fixture 1.5: 20-80 % time 1.59ns typ, 2.54ns min, 1.19ns max; typ from 1.5 V to 0.317 V
|   rising waveform, R_fixture 1000, V_fixture 1.5: 20-80 % time 4.38ns typ, 5.06ns min, 3.55ns max; typ from 0.317 V to 1.5 V
|   falling waveform, R_fixture 1000, V_fixture 0: 20-80 % time 1.98ns typ, 2.08ns min, 1.52ns max; typ from 0.636 V to 0.011 V
[GND Clamp]
| IOASDB_DC_15A
|   Voltage   I(typ)   I(min)   I(max)
-1.5V     -225.5mA   -232.3mA   -217.8mA
-1.315V   -159mA     -168.6mA   -147.6mA
-1.175V   -110.3mA   -121.8mA   -96.11mA
-1.07V    -75.34mA   -87.91mA   -59.72mA
-1V       -53.52mA   -66.39mA   -38.29mA
-940mV    -36.69mA   -49.08mA   -24.84mA
-870mV    -21.47mA   -31.19mA   -16.46mA
-800mV    -12.87mA   -17.76mA   -10.85mA
-725mV    -7.452mA   -9.662mA   -6.863mA
-590mV    -2.11mA    -2.522mA   -2.033mA
-445mV    -250.8uA   -238.2uA   -152.1uA
1.5V      322.6pA    1.07uA     -1.806uA
[POWER Clamp]
| IOASDB_DC_15A
|   Voltage   I(typ)   I(min)   I(max)
-1.5V     20.74uA    15.99uA    27.09uA
-60mV     831.2nA    644.6nA    1.085uA
-5mV      69.54nA    55.09nA    90.39nA
0V        0A         0A         0A
[Pulldown]
| IOASDB_DC_15A
|   Voltage   I(typ)   I(min)   I(max)
-1.5V     -3.011mA   -2.159mA   -4.159mA
-915mV    -2.68mA    -1.909mA   -3.737mA
-540mV    -2.125mA   -1.522mA   -2.962mA
-395mV    -1.65mA    -1.175mA   -2.284mA
510mV     1.886mA    1.252mA    2.688mA
550mV     1.835mA    1.217mA    2.834mA
570mV     1.901mA    1.259mA    2.663mA
935mV     2.996mA    1.776mA    4.507mA
1.23V     3.394mA    1.87mA     5.602mA
1.47V     3.499mA    1.919mA    5.979mA
2.33V     3.863mA    2.162mA    6.568mA
3V        4.641mA    2.641mA    7.698mA
[Pullup]
| IOASDB_DC_15A
|   Voltage   I(typ)   I(min)   I(max)
-1.5V     1.02mA     642.2uA    1.573mA
-680mV    185.2uA    120.3uA    299.3uA
575mV     -132.3uA   -89.19uA   -213.4uA
720mV     -239.2uA   -142.8uA   -425.3uA
850mV     -572.8uA   -324.1uA   -1.016mA
1.035V    -1.132mA   -663.9uA   -2.22mA
1.055V    -1.222mA   -723.6uA   -2.069mA
1.115V    -1.504mA   -911.4uA   -2.441mA
1.88V     -5.745mA   -3.846mA   -8.381mA
2.15V     -6.958mA   -4.575mA   -10.3mA
2.505V    -7.792mA   -5.135mA   -11.51mA
3V        -8.389mA   -5.557mA   -12.29mA
[Ramp]
| IOASDB_DC_15A
| variable   typ   min   max
dV/dt_r   0.37/1.57E-09   0.26/1.48E-09   0.47/1.37E-09
dV/dt_f   0.71/1.59E-09   0.60/2.54E-09   0.80/1.19E-09
R_load = 1000
[Rising Waveform]
| IOASDB_DC_15A
R_fixture =   1000
C_fixture =   0
L_fixture =   0
V_fixture =   0
V_fixture_min = 0
V_fixture_max = 0
|   Time   V(typ)   V(min)   V(max)
0s        11.11mV    9.751mV    13.53mV
295ps     32.42mV    22.23mV    47.03mV
655ps     96.2mV     62.19mV    141mV
1.795ns   419.4mV    281.9mV    582mV
2.36ns    508.8mV    360.4mV    678.9mV
3.6ns     574.2mV    414.3mV    749.1mV
5.8ns     592.8mV    442.2mV    790.5mV
39.66ns   598.8mV    446.8mV    793.6mV
57.26ns   634.2mV    446.8mV    793.7mV
240ns     635.6mV    446.9mV    794mV
[Falling Waveform]
| IOASDB_DC_15A
R_fixture =   1000
C_fixture =   0
L_fixture =   0
V_fixture =   1.5
V_fixture_min = 1.4
V_fixture_max = 1.6
|   Time   V(typ)   V(min)   V(max)
0s        1.5V       1.4V       1.6V
1.545ns   1.496V     1.399V     1.56V
2.035ns   1.395V     1.39V      1.247V
2.68ns    992.5mV    1.223V     717.1mV
3.41ns    663.2mV    961.8mV    458mV
4.045ns   522.5mV    789.2mV    373.4mV
4.855ns   435.5mV    648.1mV    310.2mV
6.93ns    349.9mV    494.9mV    263.5mV
19.6ns    317mV      399.7mV    258.7mV
240ns     316.9mV    398.9mV    258.6mV
[Rising Waveform]
| IOASDB_DC_15A
R_fixture =   1000
C_fixture =   0
L_fixture =   0
V_fixture =   1.5
V_fixture_min = 1.4
V_fixture_max = 1.6
|   Time   V(typ)   V(min)   V(max)
0s        316.9mV    398.9mV    258.5mV
545ps     381.9mV    438.4mV    356mV
1.695ns   708.9mV    660.6mV    800.5mV
2.44ns    840.7mV    780.8mV    992.9mV
3.39ns    1.012V     894.6mV    1.177V
4.43ns    1.155V     1.024V     1.317V
7.47ns    1.376V     1.254V     1.514V
12.05ns   1.474V     1.364V     1.585V
26.23ns   1.499V     1.399V     1.6V
240ns     1.5V       1.4V       1.6V
[Falling Waveform]
| IOASDB_DC_15A
R_fixture =   1000
C_fixture =   0
L_fixture =   0
V_fixture =   0
V_fixture_min = 0
V_fixture_max = 0
|   Time   V(typ)   V(min)   V(max)
0s        635.6mV    447.1mV    794mV
1.075ns   627.3mV    439.6mV    783mV
1.45ns    613.1mV    433.3mV    746mV
1.985ns   532.3mV    397.2mV    591.7mV
2.785ns   305.7mV    260.8mV    281.6mV
3.605ns   173.2mV    153.5mV    144.1mV
5.07ns    86.43mV    64.48mV    53.9mV
7.655ns   34.06mV    21.74mV    25.92mV
30.96ns   13.62mV    10.72mV    15.41mV
240ns     11.37mV    10.03mV    13.74mV
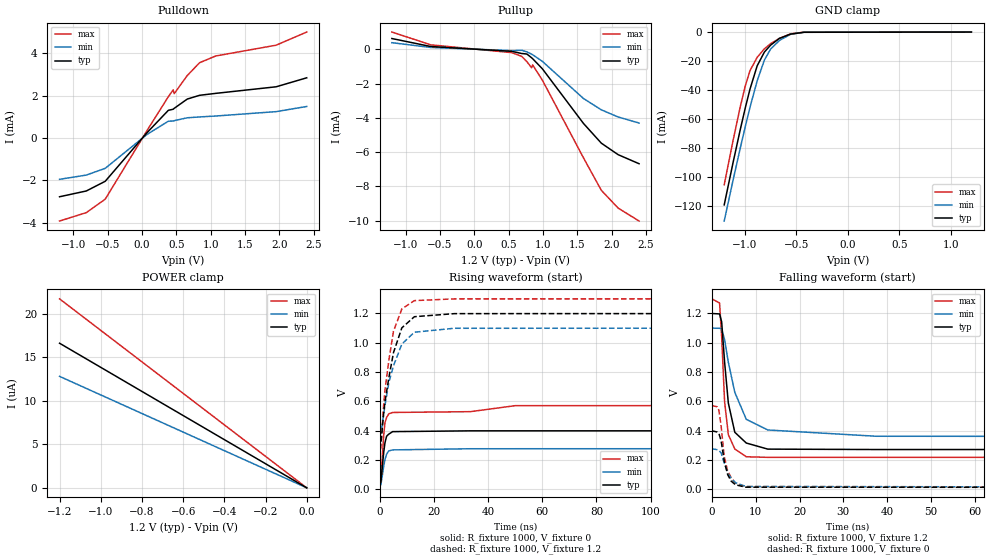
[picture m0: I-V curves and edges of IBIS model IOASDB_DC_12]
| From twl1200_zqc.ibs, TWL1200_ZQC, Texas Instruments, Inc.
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[Model]   IOASDB_DC_12
Model_type  I/O
Vinl=0.24
Vinh=0.96
Enable   Active-Low
Vref =   1.2
Rref =   1M
Cref =   15p
Vmeas =   0.6
| variable   typ   min   max
C_comp   3.98pF   3.44pF   4.66pF
| C_pullup   3.99pF   3.41pF   4.47pF
| C_pulldown   4.29pF   3.52pF   4.87pF
| C_tri-state   3.98pF   3.44pF   4.66pF
[Temperature Range]   40   100   -40
| Ambient temperature   25   85   -40
[Voltage range]   1.2   1.1   1.3
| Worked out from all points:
|   slope of the pulldown table from 0 to 0.18 V, typ, clamps not added: 272 ohm
|   slope of the pullup table from 0 to 0.18 V, typ, clamps not added: 4.5 kohm
|   GND clamp passes 1 mA (typ) near -0.53 V on its own axis
|   rising waveform, R_fixture 1000, V_fixture 0: 20-80 % time 1.31ns typ, 1.49ns min, 1.37ns max; typ from 0.009 V to 0.398 V
|   falling waveform, R_fixture 1000, V_fixture 1.2: 20-80 % time 1.94ns typ, 3.9ns min, 1.24ns max; typ from 1.2 V to 0.27 V
|   rising waveform, R_fixture 1000, V_fixture 1.2: 20-80 % time 5.03ns typ, 5.71ns min, 4.16ns max; typ from 0.27 V to 1.2 V
|   falling waveform, R_fixture 1000, V_fixture 0: 20-80 % time 1.59ns typ, 2.3ns min, 1.59ns max; typ from 0.398 V to 0.009 V
[GND Clamp]
| IOASDB_DC_12
|   Voltage   I(typ)   I(min)   I(max)
-1.2V     -118.9mA   -130mA     -105.1mA
-1.115V   -90.07mA   -102.2mA   -74.93mA
-1.045V   -67.35mA   -80.09mA   -51.64mA
-995mV    -52.03mA   -64.9mA    -36.94mA
-950mV    -39.32mA   -51.86mA   -26.6mA
-880mV    -23.22mA   -33.52mA   -17.4mA
-810mV    -13.78mA   -19.31mA   -11.53mA
-750mV    -9.045mA   -11.77mA   -8.009mA
-665mV    -4.38mA    -5.831mA   -4.423mA
-555mV    -1.418mA   -1.522mA   -1.23mA
-425mV    -166.4uA   -161.6uA   -98.99uA
1.2V      289.9pA    1.07uA     -1.806uA
[POWER Clamp]
| IOASDB_DC_12
|   Voltage   I(typ)   I(min)   I(max)
-1.2V     16.59uA    12.79uA    21.68uA
-60mV     831nA      644.3nA    1.084uA
-5mV      69.5nA     55.02nA    90.38nA
0V        0A         0A         0A
[Pulldown]
| IOASDB_DC_12
|   Voltage   I(typ)   I(min)   I(max)
-1.2V     -2.77mA    -1.949mA   -3.913mA
-810mV    -2.497mA   -1.748mA   -3.517mA
-535mV    -2.041mA   -1.431mA   -2.884mA
75mV      254.2uA    169uA      356.1uA
385mV     1.304mA    791.2uA    1.947mA
455mV     1.354mA    797.8uA    2.266mA
470mV     1.397mA    816.5uA    2.088mA
660mV     1.833mA    950.7uA    2.943mA
840mV     2.011mA    991.4uA    3.547mA
1.075V    2.102mA    1.035mA    3.864mA
1.955V    2.412mA    1.241mA    4.372mA
2.4V      2.835mA    1.483mA    4.992mA
[Pullup]
| IOASDB_DC_12
|   Voltage   I(typ)   I(min)   I(max)
-1.2V     622.8uA    381.2uA    1.002mA
-635mV    158.2uA    102.5uA    255.8uA
545mV     -124.2uA   -83.29uA   -199.9uA
690mV     -249.6uA   -61.51uA   -414.8uA
765mV     -279.4uA   -154.5uA   -718.6uA
835mV     -498.3uA   -289.8uA   -1.082mA
850mV     -552.3uA   -323.7uA   -916uA
990mV     -1.134mA   -703uA     -1.793mA
1.59V     -4.327mA   -2.874mA   -6.332mA
1.85V     -5.479mA   -3.535mA   -8.227mA
2.095V    -6.15mA    -3.953mA   -9.266mA
2.4V      -6.679mA   -4.305mA   -10.02mA
[Ramp]
| IOASDB_DC_12
| variable   typ   min   max
dV/dt_r   0.23/1.31E-09   0.16/1.49E-09   0.34/1.37E-09
dV/dt_f   0.56/1.94E-09   0.45/3.90E-09   0.65/1.24E-09
R_load = 1000
[Rising Waveform]
| IOASDB_DC_12
R_fixture =   1000
C_fixture =   0
L_fixture =   0
V_fixture =   0
V_fixture_min = 0
V_fixture_max = 0
|   Time   V(typ)   V(min)   V(max)
0s        9.248mV    8.199mV    11.23mV
515ps     51.54mV    32.17mV    78.52mV
1.545ns   251.4mV    156.3mV    370mV
2ns       315.7mV    201.8mV    453.3mV
2.61ns    361.1mV    238mV      489.3mV
3.395ns   375.1mV    260.9mV    514.2mV
4.825ns   392.5mV    267.6mV    523.5mV
33.52ns   397.9mV    275.5mV    529mV
50.14ns   397.9mV    275.5mV    570.2mV
240ns     397.9mV    275.6mV    570.6mV
[Falling Waveform]
| IOASDB_DC_12
R_fixture =   1000
C_fixture =   0
L_fixture =   0
V_fixture =   1.2
V_fixture_min = 1.1
V_fixture_max = 1.3
|   Time   V(typ)   V(min)   V(max)
0s        1.2V       1.1V       1.3V
1.76ns    1.197V     1.099V     1.272V
2.235ns   1.143V     1.095V     1.041V
2.905ns   867.7mV    1.022V     596.8mV
3.76ns    587.6mV    866.4mV    372mV
5.235ns   388.1mV    661.1mV    273.7mV
7.85ns    314.6mV    476.6mV    220.8mV
12.77ns   272.9mV    403.8mV    216.7mV
37.53ns   270.2mV    360.9mV    216.7mV
240ns     270.2mV    358mV      216.7mV
[Rising Waveform]
| IOASDB_DC_12
R_fixture =   1000
C_fixture =   0
L_fixture =   0
V_fixture =   1.2
V_fixture_min = 1.1
V_fixture_max = 1.3
|   Time   V(typ)   V(min)   V(max)
0s        270.2mV    358mV      216.7mV
515ps     314mV      382.2mV    286.1mV
1.475ns   507.9mV    503.9mV    565.8mV
1.99ns    593.8mV    570.9mV    673.4mV
3.495ns   767.2mV    732.7mV    887.2mV
5.155ns   933.1mV    842.9mV    1.079V
8.23ns    1.102V     990.8mV    1.231V
12.85ns   1.178V     1.072V     1.288V
27.56ns   1.199V     1.099V     1.3V
240ns     1.2V       1.1V       1.3V
[Falling Waveform]
| IOASDB_DC_12
R_fixture =   1000
C_fixture =   0
L_fixture =   0
V_fixture =   0
V_fixture_min = 0
V_fixture_max = 0
|   Time   V(typ)   V(min)   V(max)
0s        398.1mV    275.6mV    570.7mV
1.22ns    389.9mV    268.9mV    562.4mV
1.605ns   380.3mV    265.2mV    538.3mV
2.12ns    328.9mV    246.1mV    428.2mV
2.825ns   191mV      177.6mV    221.4mV
3.62ns    98.04mV    111.8mV    121.8mV
4.385ns   54.81mV    73.3mV     79.01mV
5.4ns     28.88mV    43.44mV    39.69mV
7.755ns   12.75mV    17.48mV    16.65mV
240ns     9.444mV    8.237mV    11.41mV
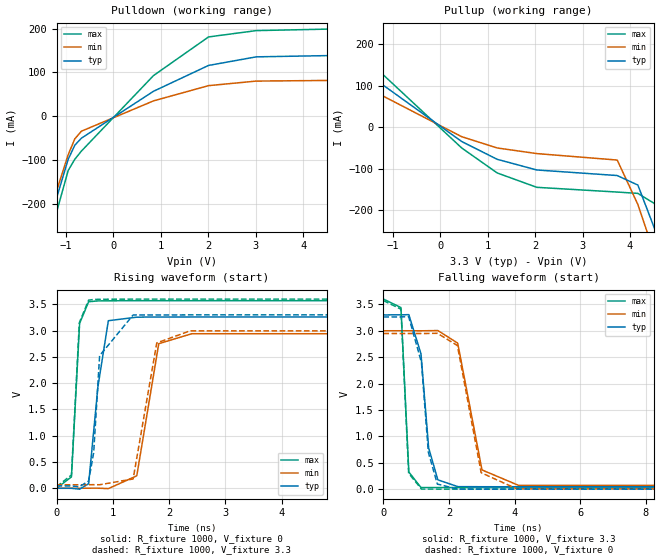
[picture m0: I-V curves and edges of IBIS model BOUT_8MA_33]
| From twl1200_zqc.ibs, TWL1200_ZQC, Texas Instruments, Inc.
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[Model]   BOUT_8MA_33
Model_type  Output
Vref =   3.3
Rref =   1M
Cref =   15p
Vmeas =   1.65
| variable   typ   min   max
C_comp   3.82pF   2.65pF   5.22pF
| C_pullup   4.11pF   2.65pF   5.22pF
| C_pulldown   3.52pF   2.93pF   4.67pF
[Temperature Range]   40   100   -40
| Ambient temperature   25   85   -40
[Voltage range]   3.3   3   3.6
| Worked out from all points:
|   slope of the pulldown table from 0 to 0.495 V, typ, clamps not added: 14.4 ohm
|   slope of the pullup table from 0 to 0.495 V, typ, clamps not added: 13.1 ohm
|   rising waveform, R_fixture 1000, V_fixture 0: 20-80 % time 117ps typ, 207ps min, 80.4ps max; typ from 0 V to 3.26 V
|   falling waveform, R_fixture 1000, V_fixture 3.3: 20-80 % time 268ps typ, 437ps min, 117ps max; typ from 3.3 V to 0.045 V
|   rising waveform, R_fixture 1000, V_fixture 3.3: 20-80 % time 115ps typ, 205ps min, 78.5ps max; typ from 0.045 V to 3.3 V
|   falling waveform, R_fixture 1000, V_fixture 0: 20-80 % time 251ps typ, 429ps min, 116ps max; typ from 3.26 V to 0 V
[Pulldown]
| BOUT_8MA_33
|   Voltage   I(typ)   I(min)   I(max)
-3.3V     -1.028A    -954.4mA   -1.134A
-1.52V    -311.2mA   -285.7mA   -356.5mA
-1.425V   -273.7mA   -251mA     -315mA
-1.33V    -236.5mA   -216.7mA   -273.6mA
-1.25V    -205.6mA   -188.1mA   -239.1mA
-955mV    -98.82mA   -88.47mA   -124.4mA
-815mV    -66.5mA    -51.96mA   -98.57mA
-675mV    -50.36mA   -34.44mA   -79.78mA
845mV     56.74mA    34.8mA     92.58mA
2.005V    115.7mA    69.56mA    180.8mA
3.01V     135.3mA    79.96mA    195.2mA
6.6V      142.1mA    83.48mA    203.4mA
[Pullup]
| BOUT_8MA_33
|   Voltage   I(typ)   I(min)   I(max)
-3.3V     268.9mA    201.4mA    326.7mA
-2.84V    233.4mA    173.2mA    288.4mA
-2.165V   180.3mA    131.8mA    229mA
450mV     -34.68mA   -23.05mA   -50.24mA
1.2V      -77.74mA   -50.31mA   -110.7mA
2.035V    -103.5mA   -63.88mA   -145.4mA
3.73V     -116.9mA   -79.51mA   -156.8mA
4.165V    -139.9mA   -186.8mA   -160mA
4.515V    -244.5mA   -305.3mA   -184.6mA
4.69V     -307mA     -366.6mA   -231.6mA
4.885V    -378.6mA   -435.8mA   -303.5mA
6.6V      -1.036A    -1.064A    -994.7mA
[Ramp]
| BOUT_8MA_33
| variable   typ   min   max
dV/dt_r   1.97/1.20E-10   1.78/2.19E-10   2.15/8.60E-11
dV/dt_f   1.96/2.75E-10   1.76/4.45E-10   2.15/1.26E-10
R_load = 1000
[Rising Waveform]
| BOUT_8MA_33
R_fixture =   1000
C_fixture =   0
L_fixture =   0
V_fixture =   0
V_fixture_min = 0
V_fixture_max = 0
|   Time   V(typ)   V(min)   V(max)
0s        10.76nV    37.36nV    1.017nV
265ps     -494.9uV   -50.69uV   216.1mV
410ps     -17.35mV   56.18uV    3.138V
570ps     86.67mV    1.202mV    3.549V
735ps     1.93V      1.792mV    3.565V
920ps     3.188V     -7.015mV   3.567V
1.425ns   3.256V     237.1mV    3.569V
1.815ns   3.258V     2.751V     3.569V
2.4ns     3.259V     2.94V      3.57V
238.2ns   3.261V     2.947V     3.571V
[Falling Waveform]
| BOUT_8MA_33
R_fixture =   1000
C_fixture =   0
L_fixture =   0
V_fixture =   3.3
V_fixture_min = 3
V_fixture_max = 3.6
|   Time   V(typ)   V(min)   V(max)
0s        3.3V       3V         3.6V
535ps     3.301V     3V         3.439V
775ps     3.305V     3V         324.7mV
1.145ns   2.564V     2.999V     31.69mV
1.38ns    777.6mV    3.001V     31mV
1.66ns    176.6mV    3.004V     30.67mV
2.265ns   48.34mV    2.765V     30.16mV
3.005ns   46.05mV    364.2mV    29.88mV
4.12ns    45.43mV    71.76mV    29.7mV
238.2ns   45.07mV    66.02mV    29.59mV
[Rising Waveform]
| BOUT_8MA_33
R_fixture =   1000
C_fixture =   0
L_fixture =   0
V_fixture =   3.3
V_fixture_min = 3
V_fixture_max = 3.6
|   Time   V(typ)   V(min)   V(max)
0s        45.07mV    66.02mV    29.59mV
265ps     44.42mV    65.97mV    252.1mV
405ps     28.68mV    66.07mV    3.15V
570ps     137.3mV    67.16mV    3.58V
660ps     680.5mV    67.93mV    3.592V
765ps     2.523V     66.53mV    3.596V
1.36ns    3.297V     177.3mV    3.599V
1.78ns    3.298V     2.765V     3.599V
2.37ns    3.299V     2.995V     3.599V
238.2ns   3.3V       3V         3.6V
[Falling Waveform]
| BOUT_8MA_33
R_fixture =   1000
C_fixture =   0
L_fixture =   0
V_fixture =   0
V_fixture_min = 0
V_fixture_max = 0
|   Time   V(typ)   V(min)   V(max)
0s        3.261V     2.947V     3.571V
535ps     3.262V     2.947V     3.409V
770ps     3.266V     2.947V     299.4mV
1.16ns    2.399V     2.947V     1.767mV
1.37ns    696.3mV    2.949V     1.269mV
1.645ns   96.19mV    2.951V     1.004mV
2.255ns   2.216mV    2.721V     538.4uV
2.98ns    847.1uV    311.3mV    280.5uV
4.065ns   331.2uV    5.454mV    117.9uV
238.2ns   43.95nV    57.27nV    5.946nV
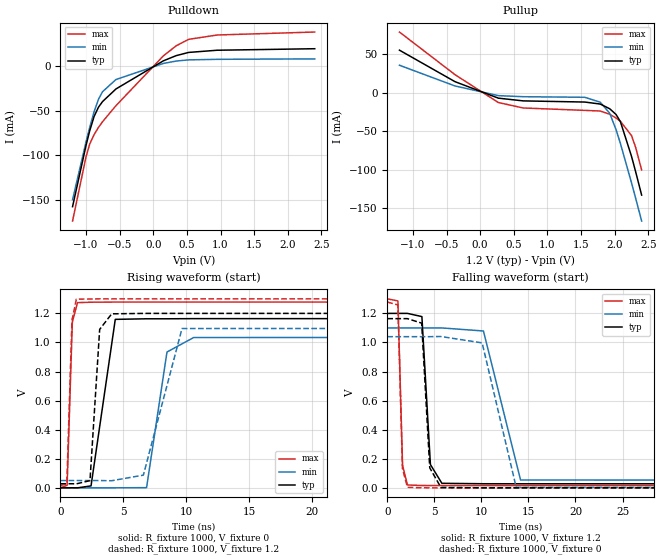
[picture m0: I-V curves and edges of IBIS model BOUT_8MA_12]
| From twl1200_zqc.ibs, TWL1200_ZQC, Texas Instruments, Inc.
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[Model]   BOUT_8MA_12
Model_type  Output
Vref =   1.2
Rref =   1M
Cref =   15p
Vmeas =   0.6
| variable   typ   min   max
C_comp   4.54pF   2.92pF   5.61pF
| C_pullup   4.58pF   2.92pF   5.50pF
| C_pulldown   4.50pF   3.14pF   5.61pF
[Temperature Range]   40   100   -40
| Ambient temperature   25   85   -40
[Voltage range]   1.2   1.1   1.3
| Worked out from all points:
|   slope of the pulldown table from 0 to 0.18 V, typ, clamps not added: 26.1 ohm
|   slope of the pullup table from 0 to 0.18 V, typ, clamps not added: 35.5 ohm
|   rising waveform, R_fixture 1000, V_fixture 0: 20-80 % time 412ps typ, 859ps min, 226ps max; typ from 0 V to 1.16 V
|   falling waveform, R_fixture 1000, V_fixture 1.2: 20-80 % time 469ps typ, 965ps min, 249ps max; typ from 1.2 V to 0.028 V
|   rising waveform, R_fixture 1000, V_fixture 1.2: 20-80 % time 404ps typ, 830ps min, 224ps max; typ from 0.028 V to 1.2 V
|   falling waveform, R_fixture 1000, V_fixture 0: 20-80 % time 455ps typ, 923ps min, 241ps max; typ from 1.16 V to 0 V
[Pulldown]
| BOUT_8MA_12
|   Voltage   I(typ)   I(min)   I(max)
-1.2V     -157.7mA   -150mA     -173.8mA
-1V       -89.15mA   -85.1mA    -101.8mA
-945mV    -72.61mA   -68.76mA   -87.44mA
-880mV    -56.56mA   -51.29mA   -76.88mA
-815mV    -46.2mA    -37.32mA   -68.85mA
-755mV    -39.91mA   -28.82mA   -62.52mA
-555mV    -25.71mA   -15.15mA   -44.45mA
150mV     5.852mA    2.921mA    11.4mA
340mV     11.65mA    5.591mA    22.69mA
525mV     15.26mA    6.91mA     29.93mA
950mV     17.72mA    7.526mA    34.81mA
2.4V      19.42mA    8.023mA    38.13mA
[Pullup]
| BOUT_8MA_12
|   Voltage   I(typ)   I(min)   I(max)
-1.2V     55.26mA    35.71mA    78.77mA
-375mV    14.44mA    8.859mA    23.55mA
270mV     -6.977mA   -3.704mA   -12.65mA
640mV     -10.53mA   -5.099mA   -19.73mA
1.555V    -12.02mA   -5.86mA    -22.82mA
1.785V    -14.64mA   -12.24mA   -23.67mA
1.925V    -20.7mA    -26.55mA   -27.77mA
2.02V     -28.15mA   -47.89mA   -32.77mA
2.085V    -37.6mA    -65.92mA   -37.02mA
2.25V     -82.55mA   -116.9mA   -55.52mA
2.31V     -102.1mA   -136.4mA   -70.56mA
2.4V      -132.7mA   -166.3mA   -100.1mA
[Ramp]
| BOUT_8MA_12
| variable   typ   min   max
dV/dt_r   0.71/4.25E-10   0.63/8.75E-10   0.78/2.37E-10
dV/dt_f   0.71/4.78E-10   0.63/9.73E-10   0.78/2.59E-10
R_load = 1000
[Rising Waveform]
| BOUT_8MA_12
R_fixture =   1000
C_fixture =   0
L_fixture =   0
V_fixture =   0
V_fixture_min = 0
V_fixture_max = 0
|   Time   V(typ)   V(min)   V(max)
0s        7.233nV    47.37nV    434.8pV
530ps     179.2uV    287.5nV    17.15mV
945ps     507.2uV    -744.4nV   1.141V
1.355ns   94.78uV    -8.298uV   1.274V
2.43ns    13.38mV    43.58uV    1.277V
4.355ns   1.159V     240.8uV    1.278V
6.84ns    1.163V     1.412mV    1.278V
8.46ns    1.163V     934.3mV    1.278V
10.58ns   1.164V     1.034V     1.278V
237.3ns   1.164V     1.04V      1.278V
[Falling Waveform]
| BOUT_8MA_12
R_fixture =   1000
C_fixture =   0
L_fixture =   0
V_fixture =   1.2
V_fixture_min = 1.1
V_fixture_max = 1.3
|   Time   V(typ)   V(min)   V(max)
0s        1.2V       1.1V       1.3V
1.125ns   1.2V       1.1V       1.286V
1.62ns    1.2V       1.1V       154.3mV
2.145ns   1.2V       1.1V       19.77mV
3.675ns   1.178V     1.1V       16.11mV
4.58ns    160.2mV    1.1V       15.87mV
5.8ns     31.17mV    1.1V       15.74mV
10.22ns   28.25mV    1.079V     15.65mV
14.16ns   28.05mV    53.94mV    15.65mV
237.3ns   28.03mV    50.18mV    15.65mV
[Rising Waveform]
| BOUT_8MA_12
R_fixture =   1000
C_fixture =   0
L_fixture =   0
V_fixture =   1.2
V_fixture_min = 1.1
V_fixture_max = 1.3
|   Time   V(typ)   V(min)   V(max)
0s        28.03mV    50.18mV    15.65mV
505ps     28.16mV    50.18mV    27.19mV
915ps     28.16mV    50.18mV    1.153V
1.265ns   27.57mV    50.17mV    1.298V
2.345ns   49.69mV    50.22mV    1.299V
3.115ns   1.09V      50.16mV    1.3V
4.07ns    1.197V     48.96mV    1.3V
6.585ns   1.2V       87.43mV    1.3V
9.655ns   1.2V       1.096V     1.3V
237.3ns   1.2V       1.1V       1.3V
[Falling Waveform]
| BOUT_8MA_12
R_fixture =   1000
C_fixture =   0
L_fixture =   0
V_fixture =   0
V_fixture_min = 0
V_fixture_max = 0
|   Time   V(typ)   V(min)   V(max)
0s        1.164V     1.04V      1.278V
1.125ns   1.164V     1.04V      1.258V
1.605ns   1.164V     1.04V      134.1mV
2.135ns   1.164V     1.04V      3.654mV
3.65ns    1.133V     1.04V      393.8uV
4.51ns    137.4mV    1.04V      201.5uV
5.695ns   2.79mV     1.041V     88.26uV
10.08ns   197.2uV    997.1mV    5.241uV
13.7ns    21.99uV    3.227mV    531.4nV
237.3ns   6.922nV    46.85nV    1.979nV
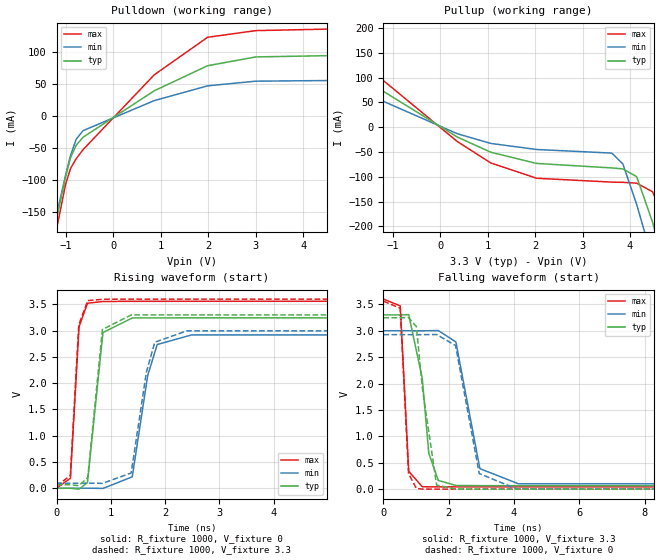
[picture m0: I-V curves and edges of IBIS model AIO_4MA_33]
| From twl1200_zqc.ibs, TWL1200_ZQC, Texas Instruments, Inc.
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[Model]   AIO_4MA_33
Model_type  Output
Vref =   3.3
Rref =   1M
Cref =   15p
Vmeas =   1.65
| variable   typ   min   max
C_comp   3.41pF   2.57pF   4.65pF
| C_pullup   3.64pF   2.57pF   4.65pF
| C_pulldown   3.18pF   2.67pF   3.75pF
[Temperature Range]   40   100   -40
| Ambient temperature   25   85   -40
[Voltage range]   3.3   3   3.6
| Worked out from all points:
|   slope of the pulldown table from 0 to 0.495 V, typ, clamps not added: 21 ohm
|   slope of the pullup table from 0 to 0.495 V, typ, clamps not added: 18.5 ohm
|   rising waveform, R_fixture 1000, V_fixture 0: 20-80 % time 143ps typ, 245ps min, 94ps max; typ from 0 V to 3.25 V
|   falling waveform, R_fixture 1000, V_fixture 3.3: 20-80 % time 270ps typ, 433ps min, 126ps max; typ from 3.3 V to 0.065 V
|   rising waveform, R_fixture 1000, V_fixture 3.3: 20-80 % time 142ps typ, 234ps min, 92.4ps max; typ from 0.065 V to 3.3 V
|   falling waveform, R_fixture 1000, V_fixture 0: 20-80 % time 246ps typ, 425ps min, 126ps max; typ from 3.25 V to 0 V
[Pulldown]
| AIO_4MA_33
|   Voltage   I(typ)   I(min)   I(max)
-3.3V     -967mA     -915.1mA   -1.042A
-1.315V   -203.4mA   -194.2mA   -223.3mA
-1.24V    -175.8mA   -168.3mA   -193.2mA
-1.18V    -154.1mA   -147.9mA   -169.4mA
-1.01V    -95.37mA   -92.33mA   -106.8mA
-905mV    -64.91mA   -61.53mA   -81.71mA
-785mV    -45.38mA   -36mA      -66.38mA
-640mV    -32.96mA   -22.68mA   -52.27mA
860mV     39.49mA    24.19mA    64.41mA
1.985V    78.6mA     47.23mA    123mA
3V        92.35mA    54.51mA    133.4mA
6.6V      97.02mA    56.91mA    139mA
[Pullup]
| AIO_4MA_33
|   Voltage   I(typ)   I(min)   I(max)
-3.3V     191.8mA    143.4mA    233.5mA
-1.57V    94.1mA     67.52mA    123.1mA
360mV     -20.05mA   -13.33mA   -29.15mA
1.065V    -50.6mA    -32.87mA   -72.33mA
2.03V     -73.21mA   -45.09mA   -103.1mA
3.615V    -82.29mA   -52.35mA   -110.9mA
3.85V     -84.27mA   -74.39mA   -111.4mA
4.14V     -99.92mA   -156mA     -113mA
4.475V    -191.7mA   -266.9mA   -130.4mA
4.69V     -266.2mA   -340.8mA   -179.4mA
4.975V    -368.6mA   -440.4mA   -282.2mA
6.6V      -975.5mA   -1.024A    -915.6mA
[Ramp]
| AIO_4MA_33
| variable   typ   min   max
dV/dt_r   1.96/1.48E-10   1.77/2.56E-10   2.15/9.65E-11
dV/dt_f   1.95/2.77E-10   1.75/4.39E-10   2.14/1.37E-10
R_load = 1000
[Rising Waveform]
| AIO_4MA_33
R_fixture =   1000
C_fixture =   0
L_fixture =   0
V_fixture =   0
V_fixture_min = 0
V_fixture_max = 0
|   Time   V(typ)   V(min)   V(max)
0s        12.35nV    41.59nV    1.376nV
255ps     298.5uV    -47.65uV   189mV
415ps     -17.67mV   70.95uV    3.073V
570ps     108.6mV    1.211mV    3.521V
855ps     2.963V     -3.191mV   3.554V
1.395ns   3.24V      217.3mV    3.557V
1.68ns    3.241V     2.148V     3.557V
1.855ns   3.241V     2.735V     3.557V
2.49ns    3.243V     2.918V     3.558V
238.2ns   3.245V     2.926V     3.559V
[Falling Waveform]
| AIO_4MA_33
R_fixture =   1000
C_fixture =   0
L_fixture =   0
V_fixture =   3.3
V_fixture_min = 3
V_fixture_max = 3.6
|   Time   V(typ)   V(min)   V(max)
0s        3.3V       3V         3.6V
515ps     3.3V       3V         3.471V
775ps     3.305V     3V         339.7mV
1.19ns    2.1V       2.999V     45.4mV
1.39ns    680.5mV    3.001V     44.53mV
1.68ns    165.9mV    3.004V     44.21mV
2.22ns    69.65mV    2.788V     43.72mV
2.955ns   66.58mV    388.6mV    43.4mV
4.14ns    65.84mV    101.3mV    43.2mV
238.2ns   65.46mV    95.69mV    43.07mV
[Rising Waveform]
| AIO_4MA_33
R_fixture =   1000
C_fixture =   0
L_fixture =   0
V_fixture =   3.3
V_fixture_min = 3
V_fixture_max = 3.6
|   Time   V(typ)   V(min)   V(max)
0s        65.46mV    95.69mV    43.07mV
255ps     65.54mV    95.64mV    240.1mV
410ps     48.95mV    95.76mV    3.111V
575ps     202.7mV    96.86mV    3.571V
845ps     3.02V      92.4mV     3.596V
1.375ns   3.297V     289.9mV    3.599V
1.655ns   3.298V     2.209V     3.599V
1.81ns    3.298V     2.779V     3.599V
2.405ns   3.299V     2.996V     3.599V
238.2ns   3.3V       3V         3.6V
[Falling Waveform]
| AIO_4MA_33
R_fixture =   1000
C_fixture =   0
L_fixture =   0
V_fixture =   0
V_fixture_min = 0
V_fixture_max = 0
|   Time   V(typ)   V(min)   V(max)
0s        3.245V     2.926V     3.559V
515ps     3.246V     2.926V     3.427V
770ps     3.25V      2.926V     296.1mV
1.01ns    3.078V     2.925V     11.61mV
1.195ns   1.904V     2.926V     1.917mV
1.63ns    76.67mV    2.929V     1.062mV
2.21ns    2.418mV    2.72V      598.6uV
2.935ns   909.7uV    296.4mV    312.6uV
4.075ns   341.9uV    5.182mV    126.8uV
238.2ns   126nV      99.07nV    16.5nV
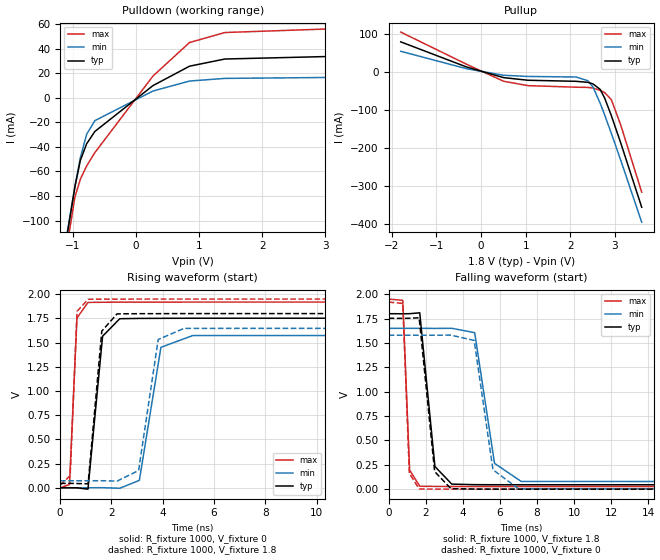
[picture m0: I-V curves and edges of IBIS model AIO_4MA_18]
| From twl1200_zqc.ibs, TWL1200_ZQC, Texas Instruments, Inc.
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[Model]   AIO_4MA_18
Model_type  Output
Vref =   1.8
Rref =   1M
Cref =   15p
Vmeas =   0.9
| variable   typ   min   max
C_comp   3.81pF   2.79pF   4.80pF
| C_pullup   4.02pF   2.79pF   4.80pF
| C_pulldown   3.61pF   3.11pF   4.17pF
[Temperature Range]   40   100   -40
| Ambient temperature   25   85   -40
[Voltage range]   1.8   1.65   1.95
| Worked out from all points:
|   slope of the pulldown table from 0 to 0.27 V, typ, clamps not added: 27.1 ohm
|   slope of the pullup table from 0 to 0.27 V, typ, clamps not added: 29.8 ohm
|   rising waveform, R_fixture 1000, V_fixture 0: 20-80 % time 268ps typ, 465ps min, 147ps max; typ from 0 V to 1.75 V
|   falling waveform, R_fixture 1000, V_fixture 1.8: 20-80 % time 328ps typ, 586ps min, 174ps max; typ from 1.8 V to 0.045 V
|   rising waveform, R_fixture 1000, V_fixture 1.8: 20-80 % time 258ps typ, 433ps min, 143ps max; typ from 0.045 V to 1.8 V
|   falling waveform, R_fixture 1000, V_fixture 0: 20-80 % time 320ps typ, 565ps min, 165ps max; typ from 1.75 V to 0 V
[Pulldown]
| AIO_4MA_18
|   Voltage   I(typ)   I(min)   I(max)
-1.8V     -370.3mA   -354.5mA   -396.6mA
-1.14V    -129.2mA   -126.6mA   -138.4mA
-1.11V    -118.9mA   -116.8mA   -127.4mA
-1.085V   -110.4mA   -108.8mA   -118.4mA
-965mV    -72.28mA   -71.82mA   -80.71mA
-880mV    -50.99mA   -48.81mA   -66.33mA
-780mV    -37.45mA   -29.7mA    -55.49mA
-650mV    -27.41mA   -18.6mA    -44.64mA
270mV     9.939mA    5.527mA    17.7mA
850mV     25.78mA    13.68mA    45.07mA
1.41V     31.63mA    15.83mA    53.22mA
3.6V      34.37mA    16.86mA    57.13mA
[Pullup]
| AIO_4MA_18
|   Voltage   I(typ)   I(min)   I(max)
-1.8V     78.87mA    54.11mA    104.5mA
-325mV    12.96mA    8.395mA    20.11mA
505mV     -15.01mA   -8.762mA   -24.48mA
1.05V     -21.87mA   -11.9mA    -35.99mA
2.13V     -24.68mA   -13.35mA   -40.12mA
2.395V    -27.3mA    -23.22mA   -40.7mA
2.51V     -31.66mA   -40.02mA   -42.3mA
2.67V     -45.89mA   -82.29mA   -48.47mA
2.77V     -68.71mA   -112.9mA   -54.47mA
2.92V     -114.8mA   -161.3mA   -72.77mA
3.13V     -186.3mA   -231.7mA   -139.3mA
3.6V      -355mA     -394.3mA   -315.4mA
[Ramp]
| AIO_4MA_18
| variable   typ   min   max
dV/dt_r   1.06/2.75E-10   0.96/4.76E-10   1.16/1.53E-10
dV/dt_f   1.06/3.39E-10   0.95/5.91E-10   1.16/1.86E-10
R_load = 1000
[Rising Waveform]
| AIO_4MA_18
R_fixture =   1000
C_fixture =   0
L_fixture =   0
V_fixture =   0
V_fixture_min = 0
V_fixture_max = 0
|   Time   V(typ)   V(min)   V(max)
0s        8.247nV    41.36nV    749.5pV
365ps     704.7uV    -744.6nV   33.77mV
655ps     -240.9uV   -22.95uV   1.754V
1.085ns   -14.22mV   21.53uV    1.915V
1.655ns   1.566V     1.021mV    1.917V
2.325ns   1.747V     -4.921mV   1.918V
3.09ns    1.75V      77.02mV    1.918V
3.93ns    1.751V     1.451V     1.918V
5.17ns    1.752V     1.573V     1.919V
238ns     1.753V     1.579V     1.919V
[Falling Waveform]
| AIO_4MA_18
R_fixture =   1000
C_fixture =   0
L_fixture =   0
V_fixture =   1.8
V_fixture_min = 1.65
V_fixture_max = 1.95
|   Time   V(typ)   V(min)   V(max)
0s        1.8V       1.65V      1.95V
760ps     1.799V     1.65V      1.937V
1.13ns    1.8V       1.65V      195.2mV
1.675ns   1.809V     1.65V      30.01mV
2.495ns   232mV      1.649V     28.13mV
3.405ns   51.76mV    1.65V      27.72mV
4.64ns    46.21mV    1.605V     27.52mV
5.71ns    45.53mV    265mV      27.46mV
7.15ns    45.25mV    78.96mV    27.42mV
238ns     45.1mV     72.71mV    27.4mV
[Rising Waveform]
| AIO_4MA_18
R_fixture =   1000
C_fixture =   0
L_fixture =   0
V_fixture =   1.8
V_fixture_min = 1.65
V_fixture_max = 1.95
|   Time   V(typ)   V(min)   V(max)
0s        45.1mV     72.71mV    27.4mV
390ps     45.84mV    72.71mV    125.2mV
660ps     44.17mV    72.69mV    1.823V
1.09ns    40.65mV    72.77mV    1.948V
1.625ns   1.619V     73mV       1.949V
2.22ns    1.797V     68.83mV    1.949V
3.06ns    1.799V     178.7mV    1.95V
3.825ns   1.799V     1.532V     1.95V
4.83ns    1.8V       1.647V     1.95V
238ns     1.8V       1.65V      1.95V
[Falling Waveform]
| AIO_4MA_18
R_fixture =   1000
C_fixture =   0
L_fixture =   0
V_fixture =   0
V_fixture_min = 0
V_fixture_max = 0
|   Time   V(typ)   V(min)   V(max)
0s        1.753V     1.579V     1.919V
760ps     1.752V     1.579V     1.905V
1.115ns   1.753V     1.579V     162.1mV
1.645ns   1.758V     1.579V     2.161mV
2.48ns    180.5mV    1.579V     615.8uV
3.355ns   5.957mV    1.58V      290.6uV
4.61ns    919.9uV    1.526V     113.5uV
5.625ns   399.2uV    199.3mV    56.45uV
6.99ns    157uV      5.45mV     22.82uV
238ns     30.15nV    52.04nV    17.88nV
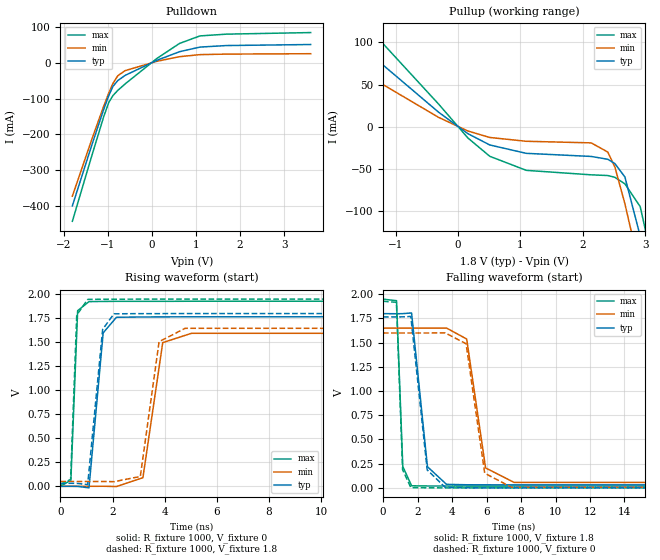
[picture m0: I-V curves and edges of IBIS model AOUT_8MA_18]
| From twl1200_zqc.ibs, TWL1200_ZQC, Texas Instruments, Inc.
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[Model]   AOUT_8MA_18
Model_type  Output
Vref =   1.8
Rref =   1M
Cref =   15p
Vmeas =   0.9
| variable   typ   min   max
C_comp   4.37pF   2.85pF   5.56pF
| C_pullup   4.60pF   2.85pF   5.56pF
| C_pulldown   4.13pF   3.05pF   5.23pF
[Temperature Range]   40   100   -40
| Ambient temperature   25   85   -40
[Voltage range]   1.8   1.65   1.95
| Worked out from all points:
|   slope of the pulldown table from 0 to 0.27 V, typ, clamps not added: 18.6 ohm
|   slope of the pullup table from 0 to 0.27 V, typ, clamps not added: 21.1 ohm
|   rising waveform, R_fixture 1000, V_fixture 0: 20-80 % time 229ps typ, 400ps min, 125ps max; typ from 0 V to 1.77 V
|   falling waveform, R_fixture 1000, V_fixture 1.8: 20-80 % time 340ps typ, 604ps min, 180ps max; typ from 1.8 V to 0.031 V
|   rising waveform, R_fixture 1000, V_fixture 1.8: 20-80 % time 223ps typ, 381ps min, 122ps max; typ from 0.031 V to 1.8 V
|   falling waveform, R_fixture 1000, V_fixture 0: 20-80 % time 333ps typ, 584ps min, 173ps max; typ from 1.77 V to 0 V
[Pulldown]
| AOUT_8MA_18
|   Voltage   I(typ)   I(min)   I(max)
-1.8V     -398.9mA   -371.9mA   -441.9mA
-1.365V   -231.8mA   -215.8mA   -261.5mA
-1.09V    -130.5mA   -121.4mA   -150.7mA
-975mV    -91.89mA   -84.7mA    -111mA
-880mV    -66.2mA    -57.88mA   -91.81mA
-770mV    -50mA      -36.46mA   -77.27mA
-605mV    -35.67mA   -22.46mA   -59.46mA
110mV     6.157mA    3.454mA    11.02mA
630mV     30.38mA    16.52mA    53.46mA
1.09V     43.16mA    22.18mA    74.23mA
1.695V    47.46mA    23.65mA    79.22mA
3.6V      50.33mA    24.73mA    83.6mA
[Pullup]
| AOUT_8MA_18
|   Voltage   I(typ)   I(min)   I(max)
-1.8V     110.8mA    76.17mA    146.6mA
-310mV    17.42mA    11.3mA     27.04mA
160mV     -7.986mA   -4.814mA   -13.09mA
510mV     -21.33mA   -12.47mA   -34.73mA
1.095V    -31.23mA   -16.97mA   -51.35mA
2.135V    -34.9mA    -18.85mA   -56.64mA
2.4V      -38.24mA   -29.69mA   -57.46mA
2.515V    -43.37mA   -47.5mA    -59.6mA
2.675V    -59.17mA   -90.8mA    -67.32mA
2.92V     -129.1mA   -169.5mA   -94.21mA
3.135V    -204.1mA   -242.6mA   -165.3mA
3.6V      -375.3mA   -406.2mA   -345.8mA
[Ramp]
| AOUT_8MA_18
| variable   typ   min   max
dV/dt_r   1.07/2.43E-10   0.97/4.13E-10   1.17/1.26E-10
dV/dt_f   1.07/3.47E-10   0.97/6.11E-10   1.16/1.98E-10
R_load = 1000
[Rising Waveform]
| AOUT_8MA_18
R_fixture =   1000
C_fixture =   0
L_fixture =   0
V_fixture =   0
V_fixture_min = 0
V_fixture_max = 0
|   Time   V(typ)   V(min)   V(max)
0s        7.131nV    37.03nV    538.1pV
400ps     880.7uV    -1.377uV   64.37mV
660ps     -241.3uV   -22.48uV   1.83V
1.095ns   -15.89mV   28.06uV    1.924V
1.64ns    1.599V     1.017mV    1.926V
2.15ns    1.761V     -1.95mV    1.927V
3.165ns   1.764V     89.94mV    1.927V
3.925ns   1.765V     1.497V     1.927V
5.03ns    1.766V     1.594V     1.928V
238ns     1.766V     1.6V       1.928V
[Falling Waveform]
| AOUT_8MA_18
R_fixture =   1000
C_fixture =   0
L_fixture =   0
V_fixture =   1.8
V_fixture_min = 1.65
V_fixture_max = 1.95
|   Time   V(typ)   V(min)   V(max)
0s        1.8V       1.65V      1.95V
780ps     1.799V     1.65V      1.934V
1.145ns   1.8V       1.65V      221.1mV
1.655ns   1.807V     1.65V      21.61mV
2.575ns   218.3mV    1.65V      19.46mV
3.68ns    36.34mV    1.651V     19.06mV
4.85ns    31.94mV    1.538V     18.92mV
5.945ns   31.4mV     206.1mV    18.86mV
7.6ns     31.15mV    56.19mV    18.83mV
238ns     31.03mV    50.12mV    18.81mV
[Rising Waveform]
| AOUT_8MA_18
R_fixture =   1000
C_fixture =   0
L_fixture =   0
V_fixture =   1.8
V_fixture_min = 1.65
V_fixture_max = 1.95
|   Time   V(typ)   V(min)   V(max)
0s        31.03mV    50.12mV    18.81mV
390ps     31.76mV    50.12mV    71.63mV
625ps     31mV       50.11mV    1.784V
1.045ns   18.38mV    50.13mV    1.947V
1.62ns    1.636V     50.67mV    1.949V
2.055ns   1.797V     48.38mV    1.949V
3.065ns   1.799V     102.8mV    1.95V
3.785ns   1.799V     1.507V     1.95V
4.785ns   1.8V       1.646V     1.95V
238ns     1.8V       1.65V      1.95V
[Falling Waveform]
| AOUT_8MA_18
R_fixture =   1000
C_fixture =   0
L_fixture =   0
V_fixture =   0
V_fixture_min = 0
V_fixture_max = 0
|   Time   V(typ)   V(min)   V(max)
0s        1.766V     1.6V       1.928V
775ps     1.766V     1.6V       1.917V
1.135ns   1.767V     1.6V       186.8mV
1.61ns    1.771V     1.6V       2.57mV
2.56ns    185.7mV    1.6V       579.4uV
3.605ns   5.143mV    1.601V     240.6uV
4.815ns   818.9uV    1.489V     98.68uV
5.895ns   349.4uV    151.2mV    47uV
7.455ns   121.6uV    5.685mV    16.66uV
238ns     14.27nV    40.6nV     6.149nV
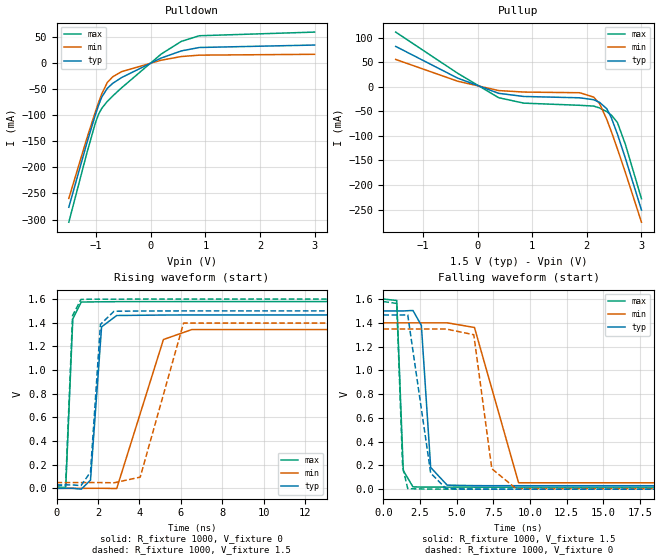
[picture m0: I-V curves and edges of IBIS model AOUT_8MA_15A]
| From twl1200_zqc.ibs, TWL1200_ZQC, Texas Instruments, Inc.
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[Model]   AOUT_8MA_15A
Model_type  Output
Vref =   1.5
Rref =   1M
Cref =   15p
Vmeas =   0.75
| variable   typ   min   max
C_comp   4.47pF   2.96pF   5.55pF
| C_pullup   4.63pF   2.96pF   5.55pF
| C_pulldown   4.31pF   3.09pF   5.32pF
[Temperature Range]   40   100   -40
| Ambient temperature   25   85   -40
[Voltage range]   1.5   1.4   1.6
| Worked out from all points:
|   slope of the pulldown table from 0 to 0.225 V, typ, clamps not added: 21.1 ohm
|   slope of the pullup table from 0 to 0.225 V, typ, clamps not added: 25.9 ohm
|   rising waveform, R_fixture 1000, V_fixture 0: 20-80 % time 290ps typ, 521ps min, 179ps max; typ from 0 V to 1.47 V
|   falling waveform, R_fixture 1000, V_fixture 1.5: 20-80 % time 375ps typ, 691ps min, 211ps max; typ from 1.5 V to 0.029 V
|   rising waveform, R_fixture 1000, V_fixture 1.5: 20-80 % time 281ps typ, 494ps min, 178ps max; typ from 0.029 V to 1.5 V
|   falling waveform, R_fixture 1000, V_fixture 0: 20-80 % time 367ps typ, 665ps min, 204ps max; typ from 1.47 V to 0 V
[Pulldown]
| AOUT_8MA_15A
|   Voltage   I(typ)   I(min)   I(max)
-1.5V     -276.5mA   -259.6mA   -305.1mA
-1.17V    -153.8mA   -144.8mA   -172.9mA
-1.015V   -99.98mA   -94.09mA   -115.5mA
-955mV    -81.21mA   -75.81mA   -98.17mA
-895mV    -65.24mA   -59.03mA   -86.99mA
-795mV    -48.88mA   -37.6mA    -73.87mA
-695mV    -39.19mA   -26.67mA   -63.34mA
-535mV    -28.25mA   -16.93mA   -47.97mA
190mV     9.114mA    4.967mA    16.66mA
560mV     22.81mA    12.03mA    41.08mA
890mV     29.34mA    14.7mA     51.85mA
3V        34.04mA    16.32mA    58.84mA
[Pullup]
| AOUT_8MA_15A
|   Voltage   I(typ)   I(min)   I(max)
-1.5V     82.17mA    55.65mA    111.3mA
-365mV    17.56mA    11.28mA    27.44mA
385mV     -13.32mA   -7.751mA   -22.27mA
845mV     -19.77mA   -10.78mA   -33.34mA
1.87V     -22.47mA   -12.17mA   -37.74mA
2.125V    -26.41mA   -21.05mA   -39.33mA
2.235V    -31.94mA   -34.69mA   -43.25mA
2.365V    -44.71mA   -66.53mA   -50.65mA
2.445V    -62.18mA   -90.19mA   -57.2mA
2.56V     -96.49mA   -126.5mA   -72.68mA
2.705V    -145.3mA   -174.4mA   -117mA
3V        -250.9mA   -275.7mA   -227.9mA
[Ramp]
| AOUT_8MA_15A
| variable   typ   min   max
dV/dt_r   0.89/2.94E-10   0.82/5.34E-10   0.96/1.84E-10
dV/dt_f   0.89/3.89E-10   0.82/7.01E-10   0.96/2.22E-10
R_load = 1000
[Rising Waveform]
| AOUT_8MA_15A
R_fixture =   1000
C_fixture =   0
L_fixture =   0
V_fixture =   0
V_fixture_min = 0
V_fixture_max = 0
|   Time   V(typ)   V(min)   V(max)
0s        6.948nV    39.69nV    474.2pV
445ps     612.6uV    -203.1nV   10.74mV
785ps     520.3uV    -11.56uV   1.433V
1.195ns   -6.814mV   -35.11uV   1.575V
1.64ns    69.6mV     436uV      1.576V
2.175ns   1.365V     678.2uV    1.577V
2.905ns   1.461V     -1.592mV   1.578V
5.16ns    1.465V     1.258V     1.578V
6.525ns   1.466V     1.342V     1.579V
237.8ns   1.466V     1.348V     1.579V
[Falling Waveform]
| AOUT_8MA_15A
R_fixture =   1000
C_fixture =   0
L_fixture =   0
V_fixture =   1.5
V_fixture_min = 1.4
V_fixture_max = 1.6
|   Time   V(typ)   V(min)   V(max)
0s        1.5V       1.4V       1.6V
910ps     1.5V       1.4V       1.588V
1.355ns   1.5V       1.4V       156.3mV
2.015ns   1.504V     1.4V       19.68mV
2.59ns    1.378V     1.4V       17.74mV
3.225ns   182.7mV    1.4V       17.34mV
4.35ns    33.82mV    1.4V       17.07mV
6.21ns    29.69mV    1.361V     16.94mV
9.22ns    29.08mV    53.92mV    16.9mV
237.8ns   29mV       48.8mV     16.89mV
[Rising Waveform]
| AOUT_8MA_15A
R_fixture =   1000
C_fixture =   0
L_fixture =   0
V_fixture =   1.5
V_fixture_min = 1.4
V_fixture_max = 1.6
|   Time   V(typ)   V(min)   V(max)
0s        29mV       48.8mV     16.89mV
440ps     29.55mV    48.8mV     27.46mV
775ps     29.11mV    48.79mV    1.46V
1.18ns    23.21mV    48.78mV    1.597V
1.64ns    137.6mV    49.21mV    1.599V
2.12ns    1.386V     48.88mV    1.599V
2.775ns   1.497V     47.02mV    1.599V
4.04ns    1.499V     94.82mV    1.6V
6.13ns    1.5V       1.397V     1.6V
237.8ns   1.5V       1.4V       1.6V
[Falling Waveform]
| AOUT_8MA_15A
R_fixture =   1000
C_fixture =   0
L_fixture =   0
V_fixture =   0
V_fixture_min = 0
V_fixture_max = 0
|   Time   V(typ)   V(min)   V(max)
0s        1.466V     1.348V     1.579V
910ps     1.466V     1.348V     1.563V
1.31ns    1.466V     1.348V     190.1mV
1.66ns    1.467V     1.348V     4.087mV
3.225ns   135.2mV    1.348V     392.7uV
4.27ns    4.511mV    1.348V     173.8uV
6.165ns   613.8uV    1.3V       46.91uV
7.395ns   244.9uV    171.8mV    20.92uV
9.045ns   84.68uV    4.539mV    7.195uV
237.8ns   9.08nV     40.38nV    5.166nV
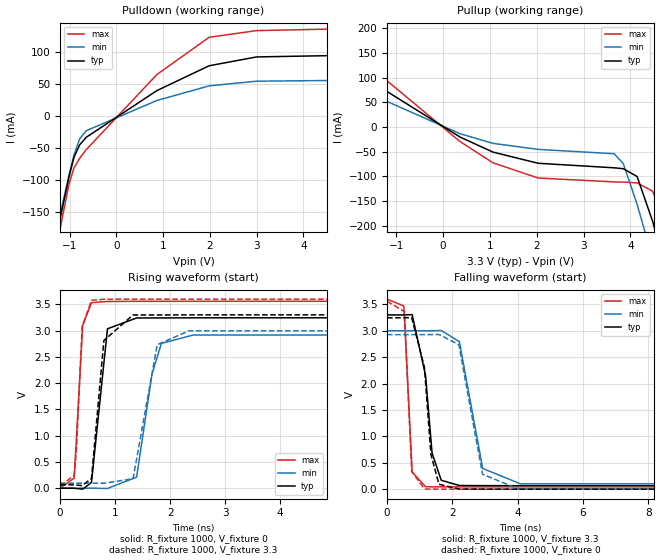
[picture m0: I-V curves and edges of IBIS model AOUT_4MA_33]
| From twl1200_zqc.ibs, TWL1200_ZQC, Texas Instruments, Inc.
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[Model]   AOUT_4MA_33
Model_type  Output
Vref =   3.3
Rref =   1M
Cref =   15p
Vmeas =   1.65
| variable   typ   min   max
C_comp   3.19pF   2.39pF   4.37pF
| C_pullup   3.42pF   2.39pF   4.37pF
| C_pulldown   2.95pF   2.51pF   3.55pF
[Temperature Range]   40   100   -40
| Ambient temperature   25   85   -40
[Voltage range]   3.3   3   3.6
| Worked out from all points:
|   slope of the pulldown table from 0 to 0.495 V, typ, clamps not added: 21 ohm
|   slope of the pullup table from 0 to 0.495 V, typ, clamps not added: 18.5 ohm
|   rising waveform, R_fixture 1000, V_fixture 0: 20-80 % time 137ps typ, 233ps min, 89.3ps max; typ from 0 V to 3.25 V
|   falling waveform, R_fixture 1000, V_fixture 3.3: 20-80 % time 263ps typ, 422ps min, 124ps max; typ from 3.3 V to 0.065 V
|   rising waveform, R_fixture 1000, V_fixture 3.3: 20-80 % time 136ps typ, 223ps min, 88.1ps max; typ from 0.065 V to 3.3 V
|   falling waveform, R_fixture 1000, V_fixture 0: 20-80 % time 239ps typ, 412ps min, 123ps max; typ from 3.25 V to 0 V
[Pulldown]
| AOUT_4MA_33
|   Voltage   I(typ)   I(min)   I(max)
-3.3V     -960.8mA   -910.2mA   -1.034A
-1.31V    -200.1mA   -191.3mA   -219.5mA
-1.235V   -172.8mA   -165.6mA   -189.6mA
-1.175V   -151.2mA   -145.3mA   -166.1mA
-1.01V    -94.6mA    -91.69mA   -105.8mA
-905mV    -64.34mA   -61.06mA   -81.02mA
-785mV    -45.04mA   -35.7mA    -65.96mA
-645mV    -33.16mA   -22.89mA   -52.54mA
865mV     39.7mA     24.32mA    64.74mA
1.985V    78.6mA     47.23mA    123mA
3V        92.35mA    54.51mA    133.4mA
6.6V      97.02mA    56.91mA    139mA
[Pullup]
| AOUT_4MA_33
|   Voltage   I(typ)   I(min)   I(max)
-3.3V     191.8mA    143.4mA    233.5mA
-1.57V    94.1mA     67.52mA    123.1mA
360mV     -20.05mA   -13.33mA   -29.15mA
1.065V    -50.6mA    -32.87mA   -72.33mA
2.03V     -73.21mA   -45.09mA   -103.1mA
3.655V    -82.42mA   -53.92mA   -111mA
3.85V     -84.22mA   -74mA      -111.4mA
4.145V    -100.1mA   -156.7mA   -113mA
4.475V    -190.6mA   -265.5mA   -129.7mA
4.69V     -264.6mA   -339mA     -178.2mA
4.97V     -364.5mA   -436.3mA   -278.4mA
6.6V      -969.3mA   -1.019A    -908.9mA
[Ramp]
| AOUT_4MA_33
| variable   typ   min   max
dV/dt_r   1.96/1.41E-10   1.77/2.46E-10   2.15/9.12E-11
dV/dt_f   1.95/2.71E-10   1.75/4.24E-10   2.14/1.35E-10
R_load = 1000
[Rising Waveform]
| AOUT_4MA_33
R_fixture =   1000
C_fixture =   0
L_fixture =   0
V_fixture =   0
V_fixture_min = 0
V_fixture_max = 0
|   Time   V(typ)   V(min)   V(max)
0s        11.62nV    39.25nV    1.342nV
255ps     289uV      -48.9uV    193.8mV
410ps     -17.57mV   58.44uV    3.098V
570ps     111.6mV    1.24mV     3.531V
860ps     3.034V     -3.586mV   3.554V
1.39ns    3.24V      210.9mV    3.557V
1.67ns    3.241V     2.169V     3.557V
1.84ns    3.241V     2.756V     3.557V
2.425ns   3.243V     2.917V     3.558V
238.2ns   3.245V     2.926V     3.559V
[Falling Waveform]
| AOUT_4MA_33
R_fixture =   1000
C_fixture =   0
L_fixture =   0
V_fixture =   3.3
V_fixture_min = 3
V_fixture_max = 3.6
|   Time   V(typ)   V(min)   V(max)
0s        3.3V       3V         3.6V
515ps     3.3V       3V         3.469V
770ps     3.305V     3V         325.7mV
1.18ns    2.153V     2.999V     45.33mV
1.38ns    683.9mV    3.001V     44.58mV
1.66ns    168.6mV    3.004V     44.23mV
2.215ns   69.36mV    2.795V     43.72mV
2.93ns    66.59mV    392.4mV    43.4mV
4.085ns   65.85mV    101.6mV    43.2mV
238.2ns   65.46mV    95.69mV    43.07mV
[Rising Waveform]
| AOUT_4MA_33
R_fixture =   1000
C_fixture =   0
L_fixture =   0
V_fixture =   3.3
V_fixture_min = 3
V_fixture_max = 3.6
|   Time   V(typ)   V(min)   V(max)
0s        65.46mV    95.69mV    43.07mV
255ps     65.52mV    95.64mV    245.1mV
300ps     60.81mV    95.63mV    795mV
400ps     49.46mV    95.73mV    3.078V
570ps     186.9mV    96.84mV    3.576V
795ps     2.811V     94.8mV     3.596V
1.325ns   3.297V     180.1mV    3.599V
1.765ns   3.298V     2.731V     3.599V
2.34ns    3.299V     2.995V     3.599V
238.2ns   3.3V       3V         3.6V
[Falling Waveform]
| AOUT_4MA_33
R_fixture =   1000
C_fixture =   0
L_fixture =   0
V_fixture =   0
V_fixture_min = 0
V_fixture_max = 0
|   Time   V(typ)   V(min)   V(max)
0s        3.245V     2.926V     3.559V
535ps     3.246V     2.926V     3.363V
755ps     3.25V      2.926V     337.9mV
1.145ns   2.309V     2.926V     2.165mV
1.345ns   657.1mV    2.927V     1.334mV
1.59ns    93.46mV    2.929V     1.104mV
2.2ns     2.322mV    2.737V     596.4uV
2.925ns   902.9uV    282.8mV    310.7uV
4.015ns   352.5uV    5.42mV     130.5uV
238.2ns   68.46nV    68.11nV    8.549nV
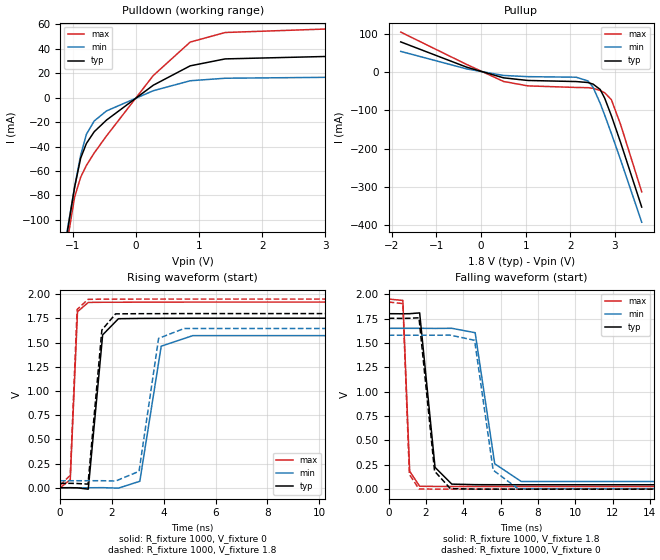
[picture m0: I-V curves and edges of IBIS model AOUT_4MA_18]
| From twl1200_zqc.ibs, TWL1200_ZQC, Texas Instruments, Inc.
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[Model]   AOUT_4MA_18
Model_type  Output
Vref =   1.8
Rref =   1M
Cref =   15p
Vmeas =   0.9
| variable   typ   min   max
C_comp   3.59pF   2.61pF   4.53pF
| C_pullup   3.80pF   2.61pF   4.53pF
| C_pulldown   3.39pF   2.86pF   3.95pF
[Temperature Range]   40   100   -40
| Ambient temperature   25   85   -40
[Voltage range]   1.8   1.65   1.95
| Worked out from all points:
|   slope of the pulldown table from 0 to 0.27 V, typ, clamps not added: 27.1 ohm
|   slope of the pullup table from 0 to 0.27 V, typ, clamps not added: 29.8 ohm
|   rising waveform, R_fixture 1000, V_fixture 0: 20-80 % time 255ps typ, 439ps min, 139ps max; typ from 0 V to 1.75 V
|   falling waveform, R_fixture 1000, V_fixture 1.8: 20-80 % time 318ps typ, 566ps min, 169ps max; typ from 1.8 V to 0.045 V
|   rising waveform, R_fixture 1000, V_fixture 1.8: 20-80 % time 246ps typ, 411ps min, 135ps max; typ from 0.045 V to 1.8 V
|   falling waveform, R_fixture 1000, V_fixture 0: 20-80 % time 310ps typ, 546ps min, 160ps max; typ from 1.75 V to 0 V
[Pulldown]
| AOUT_4MA_18
|   Voltage   I(typ)   I(min)   I(max)
-1.8V     -367.8mA   -352.4mA   -393.4mA
-1.105V   -116.2mA   -114.4mA   -124.4mA
-1.08V    -107.8mA   -106.4mA   -115.5mA
-970mV    -73.05mA   -72.7mA    -81.1mA
-875mV    -49.51mA   -47.17mA   -65.1mA
-785mV    -37.59mA   -30.08mA   -55.54mA
-660mV    -27.87mA   -19.08mA   -45.23mA
-465mV    -18.35mA   -10.87mA   -31.3mA
275mV     10.11mA    5.62mA     18.01mA
860mV     25.97mA    13.77mA    45.39mA
1.415V    31.65mA    15.84mA    53.24mA
3.6V      34.37mA    16.86mA    57.13mA
[Pullup]
| AOUT_4MA_18
|   Voltage   I(typ)   I(min)   I(max)
-1.8V     78.87mA    54.11mA    104.5mA
-325mV    12.96mA    8.395mA    20.11mA
505mV     -15.01mA   -8.762mA   -24.48mA
1.05V     -21.87mA   -11.9mA    -35.99mA
2.13V     -24.68mA   -13.34mA   -40.12mA
2.395V    -27.21mA   -22.98mA   -40.69mA
2.51V     -31.44mA   -39.61mA   -42.22mA
2.67V     -45.39mA   -81.64mA   -48.16mA
2.77V     -68.02mA   -112.1mA   -53.98mA
2.92V     -113.8mA   -160.3mA   -71.92mA
3.13V     -184.8mA   -230.2mA   -137.9mA
3.6V      -352.5mA   -392mA     -312.6mA
[Ramp]
| AOUT_4MA_18
| variable   typ   min   max
dV/dt_r   1.06/2.64E-10   0.96/4.50E-10   1.16/1.44E-10
dV/dt_f   1.06/3.29E-10   0.95/5.75E-10   1.16/1.79E-10
R_load = 1000
[Rising Waveform]
| AOUT_4MA_18
R_fixture =   1000
C_fixture =   0
L_fixture =   0
V_fixture =   0
V_fixture_min = 0
V_fixture_max = 0
|   Time   V(typ)   V(min)   V(max)
0s        7.719nV    38.74nV    738.7pV
390ps     887uV      -1.36uV    83.71mV
670ps     -589.5uV   -25uV      1.82V
1.085ns   -14.44mV   22.78uV    1.915V
1.64ns    1.58V      1.062mV    1.917V
2.25ns    1.747V     -3.663mV   1.917V
3.075ns   1.75V      67.29mV    1.918V
3.9ns     1.751V     1.463V     1.918V
5.115ns   1.752V     1.572V     1.919V
238ns     1.753V     1.579V     1.919V
[Falling Waveform]
| AOUT_4MA_18
R_fixture =   1000
C_fixture =   0
L_fixture =   0
V_fixture =   1.8
V_fixture_min = 1.65
V_fixture_max = 1.95
|   Time   V(typ)   V(min)   V(max)
0s        1.8V       1.65V      1.95V
760ps     1.799V     1.65V      1.936V
1.125ns   1.8V       1.65V      184.2mV
1.66ns    1.808V     1.65V      30.04mV
2.485ns   224mV      1.649V     28.13mV
3.385ns   51.65mV    1.65V      27.72mV
4.635ns   46.18mV    1.605V     27.52mV
5.685ns   45.53mV    260.3mV    27.46mV
7.105ns   45.25mV    78.9mV     27.42mV
238ns     45.1mV     72.71mV    27.4mV
[Rising Waveform]
| AOUT_4MA_18
R_fixture =   1000
C_fixture =   0
L_fixture =   0
V_fixture =   1.8
V_fixture_min = 1.65
V_fixture_max = 1.95
|   Time   V(typ)   V(min)   V(max)
0s        45.1mV     72.71mV    27.4mV
390ps     45.85mV    72.71mV    128.7mV
655ps     44.23mV    72.69mV    1.843V
1.075ns   37.58mV    72.75mV    1.947V
1.61ns    1.63V      73.05mV    1.949V
2.14ns    1.797V     69.59mV    1.949V
3.045ns   1.799V     170mV      1.95V
3.8ns     1.799V     1.544V     1.95V
4.785ns   1.8V       1.646V     1.95V
238ns     1.8V       1.65V      1.95V
[Falling Waveform]
| AOUT_4MA_18
R_fixture =   1000
C_fixture =   0
L_fixture =   0
V_fixture =   0
V_fixture_min = 0
V_fixture_max = 0
|   Time   V(typ)   V(min)   V(max)
0s        1.753V     1.579V     1.919V
760ps     1.752V     1.579V     1.904V
1.11ns    1.753V     1.579V     151.1mV
1.625ns   1.758V     1.579V     2.216mV
2.46ns    184.7mV    1.579V     621.3uV
3.305ns   6.027mV    1.58V      299.9uV
4.605ns   896.1uV    1.527V     112.9uV
5.6ns     397.7uV    195.3mV    56.81uV
6.925ns   160.8uV    5.486mV    23.5uV
238ns     18.15nV    44.04nV    8.147nV
